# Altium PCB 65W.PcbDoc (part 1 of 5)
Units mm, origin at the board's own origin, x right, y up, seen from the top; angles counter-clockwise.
Board outline 240.2 x 292.5 mm, 2 copper layers (Top Layer, Bottom Layer); 57 components, 0 nets, 145 pads, 8 vias.

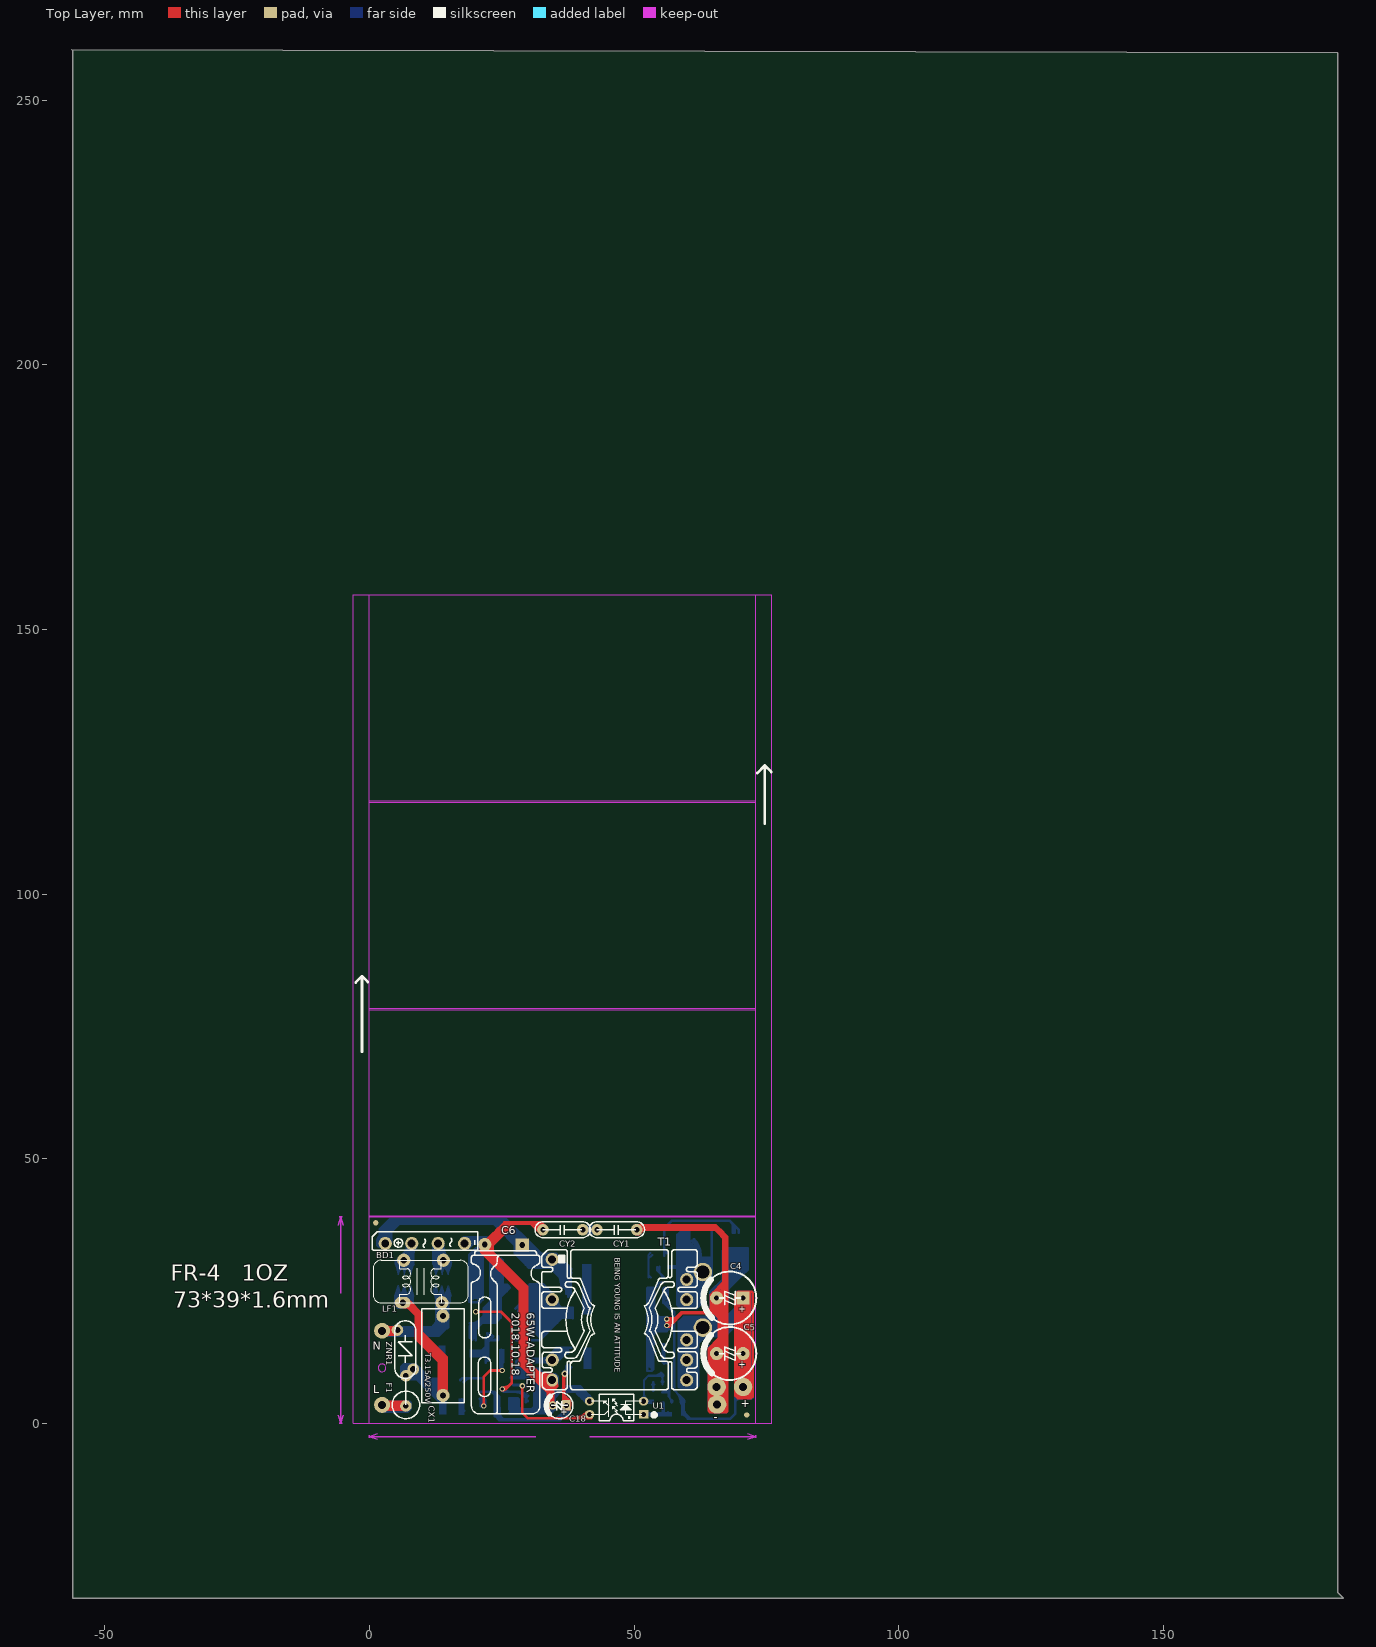
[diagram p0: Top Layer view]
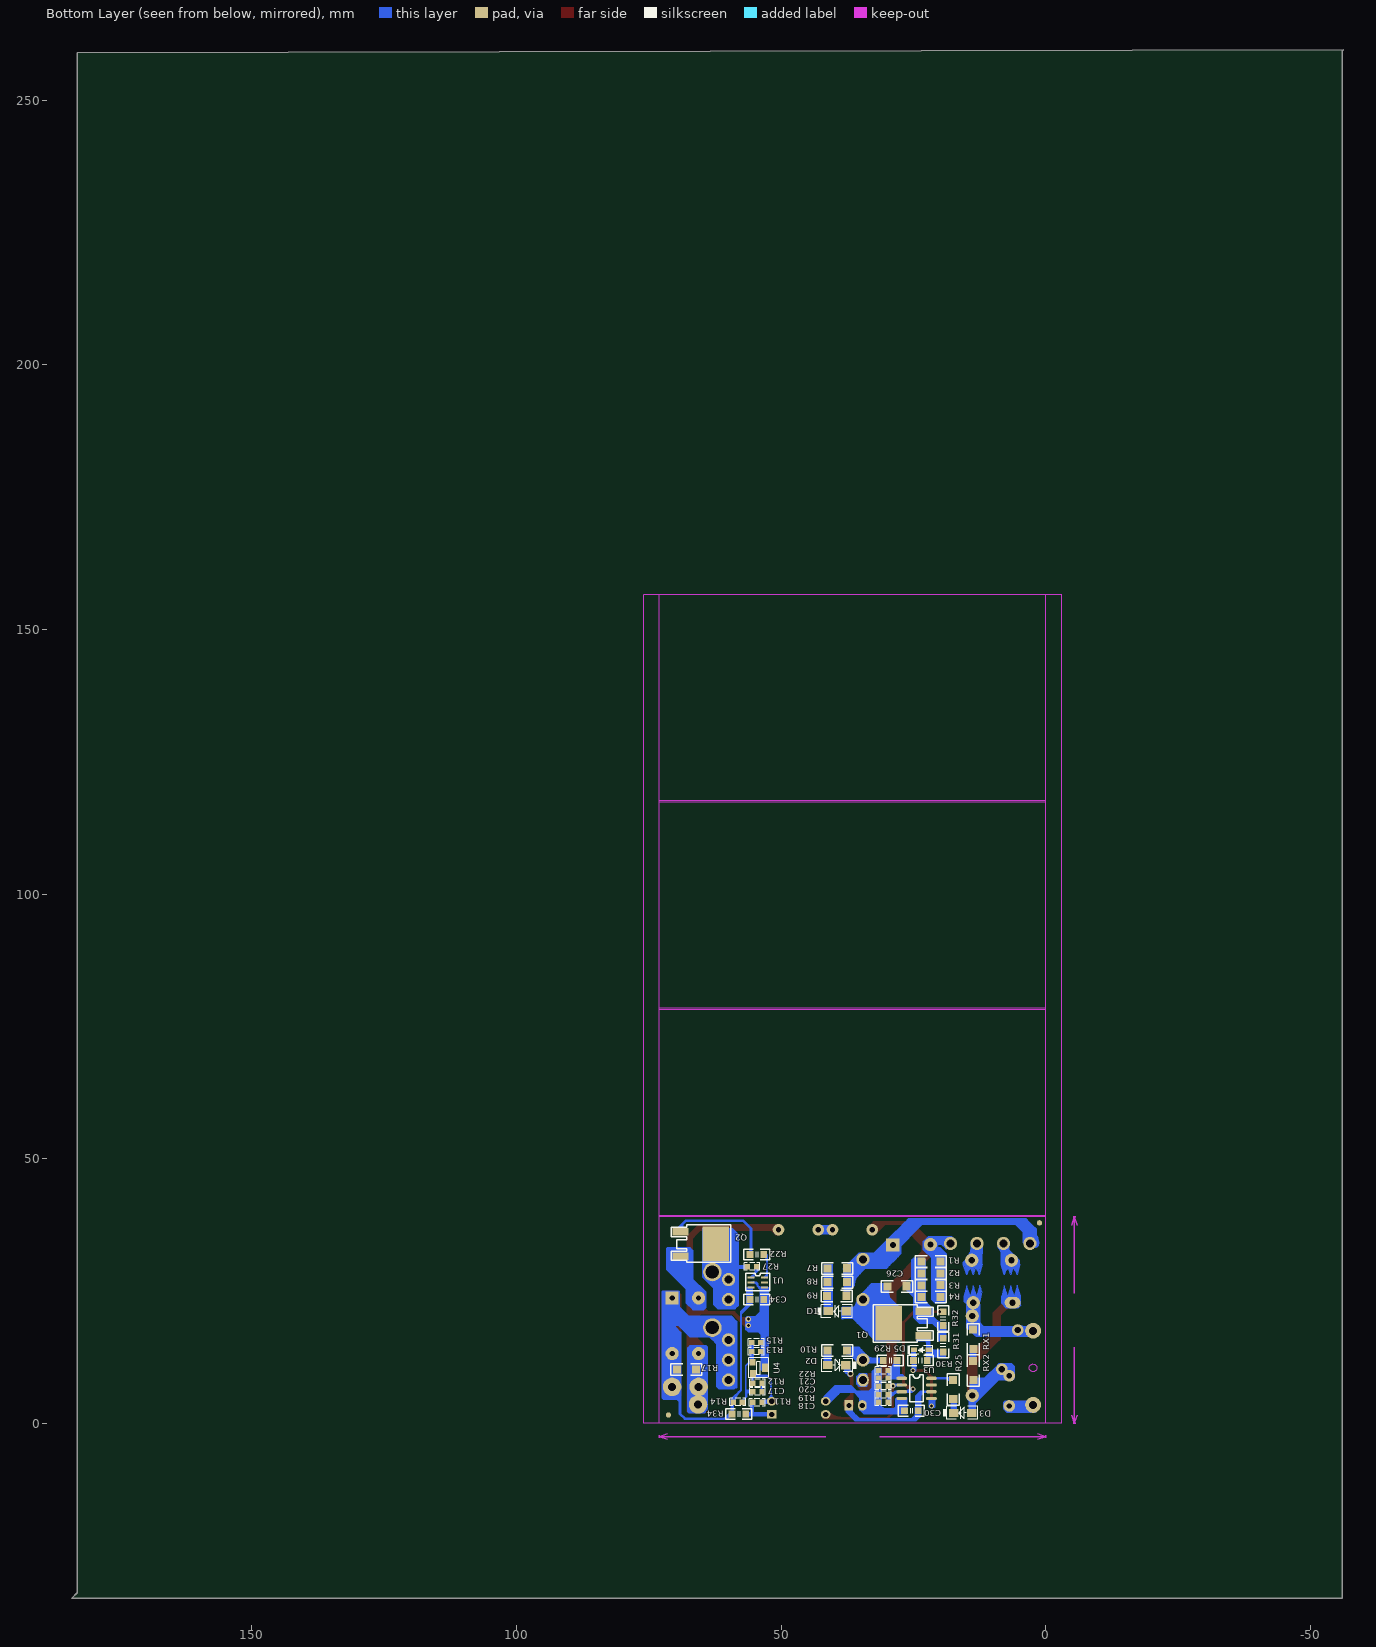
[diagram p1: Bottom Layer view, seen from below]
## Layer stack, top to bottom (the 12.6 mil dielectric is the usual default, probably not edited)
Top Layer: signal copper 0.0356
Dielectric: dielectric 0.32, FR-4, Dk 4.8
Bottom Layer: signal copper 0.0356

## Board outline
-56.2,259.5 -56,259.3 -56,-33 184,-33 183,-32 183,259

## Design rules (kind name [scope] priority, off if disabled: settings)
Clearance [All] p1: gap=0.254
PolygonConnect [All] p1: connectstyle=Relief reliefconductorwidth=0.254 reliefentries=4 polygonreliefangle="90 Angle"
RoutingVias [All] p1: holewidth=0.711 width=1.27 viastyle="Through Hole" minholewidth=0.711 minwidth=1.27 maxholewidth=0.711 maxwidth=1.27
SilkscreenOverComponentPads [All] p1: minsilkscreentomaskgap=0.254
SolderMaskExpansion [All] p1: expansion=0.102
TestPointUsage [All] p1: valid=0 allowmultiple=FALSE
Testpoint [All] p1: side=15 testpointundercomponent=TRUE minsize=1.016 maxsize=2.54 preferedsize=1.524 minholesize=0 maxholesize=1.016 preferedholesize=0.813 testpointgrid=0.025 style=1023 order=0-112345678
Width [All] p1: maxlimit=2 minlimit=0.1 preferedwidth=0.5
23 further rules are at their usual default settings.

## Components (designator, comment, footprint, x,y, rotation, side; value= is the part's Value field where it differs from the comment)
BD1 "" BD-GBL406L 3,34 r0 top
C4 "CAPACITOR+" EC10#1 70.6,23.7 r180 top
C5 "CAPACITOR+" EC10#2 70.6,13.2 r180 top (schematic designator C4)
C6 "" EC13*30 28.9,33.7 r270 top
C17 "" 0603 54.5,6 r180 bottom
C18 "CAPACITOR+" EC5 37.2,3.4 r180 top (schematic designator C9)
C18 "" 0603 30.7,4 r180 bottom
C20 "" 0603 30.7,7 r180 bottom
C21 "" 0603 30.7,8.6 r180 bottom
C26 "" 1206-S 28.1,25.9 r0 bottom
C30 "RESISTOR" 0805-S 25.4,2.4 r0 bottom (schematic designator R29)
C34 "RESISTOR" 0805-S 54.6,23.4 r0 bottom (schematic designator R29)
CX1 "CAPACITOR" C15 13.9,20.3 r270 top
CY1 "CAPACITOR" CY7.5 50.5,36.6 r180 top
CY2 "CAPACITOR" CY7.5 40.3,36.6 r180 top (schematic designator CY1)
D1 "" 4148 39.4,21.2 r180 bottom
D2 "" 4148 39.5,11 r0 bottom
D3 "" 4148 15.7,2 r180 bottom
D5 "DIODE" SOD-323 22.1,13.9 r0 bottom
F1 "FUSE" FUSE5220 6.9,3.5 r269 top
LF1 "TRANSFORMER" L18*8 13.7,22.8 r180 top
Q1 "" TO-252 23.1,16.6 r90 bottom
Q2 "" TO-252 69,36.2 r270 bottom
R1 "" 1206-S 21.7,30.6 r0 bottom
R2 "" 1206-S 21.7,28.3 r0 bottom
R3 "" 1206-S 21.7,26.1 r0 bottom
R4 "" 1206-S 21.7,23.9 r0 bottom
R7 "" 1206-S 39.4,29.3 r0 bottom
R8 "" 1206-S 39.4,26.7 r0 bottom
R9 "" 1206-S 39.5,24.1 r0 bottom
R10 "" 1206-S 39.4,13.8 r0 bottom
R11 "" 0603 54.5,4 r0 bottom
R12 "" 0603 54.5,7.6 r180 bottom
R13 "" 0603 54.7,13.6 r180 bottom
R14 "" 0603 58.2,4 r180 bottom
R15 "" 0603 54.7,15.3 r180 bottom
R17 "" 1206-S 67.9,10.2 r0 bottom
R19 "" 0603 30.7,5.4 r180 bottom
R22 "RESISTOR" 0805-S 54.6,31.9 r0 bottom (schematic designator R29)
R22 "" 0603 30.7,10 r180 bottom
R25 "" 1206-S 17.5,6.4 r90 bottom
R27 "" 0603 55.5,29.6 r180 bottom
R29 "RESISTOR" 0805-S 29.4,11.9 r0 bottom
R30 "RESISTOR" 0805-S 23.7,11.9 r180 bottom (schematic designator R29)
R31 "RESISTOR" 0805-S 19.4,14.8 r90 bottom (schematic designator R29)
R32 "RESISTOR" 0805-S 19.4,19.8 r90 bottom (schematic designator R29)
R34 "RESISTOR" 0805-S 58,1.8 r0 bottom (schematic designator R29)
RX1 "" 1206-S 13.7,15.9 r90 bottom
RX2 "" 1206-S 13.7,10 r90 bottom
T1 "" PQ2625 34.544,30.988 r0 top
U1 "PC817" oc-10.2 51.8,1.7 r180 top
U1 "" SOT23-6 55.7,27.6 r180 bottom
U3 "DIP8-L" SO-8 27.2,8.5 r180 bottom
U4 "" C1815 54.2,10.5 r270 bottom
ZNR1 "ZNR" ZNR7.5-2 5.3,10.3 r90 top
? "" ESD-1#1 13.7,27.4 r270 top
? "" ESD-1#2 6.6,27.4 r270 top

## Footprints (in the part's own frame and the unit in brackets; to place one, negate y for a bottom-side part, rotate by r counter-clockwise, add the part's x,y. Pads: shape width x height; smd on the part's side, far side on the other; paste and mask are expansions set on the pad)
0603 [mm]
  rect 1.016x1 smd: 1(-0.875,0) 2(0.875,0)
  silkscreen extent -1.48,-0.68 1.49,0.72
0805-S [mm]
  rect 1.27x1.27 smd: 1(-1.301,0) 2(1.301,0)
  silkscreen extent -2.42,-1.02 2.46,1.02
1206-S [mil]
  rect 60x60 smd: 1(-71.44,-0.61) 2(71.44,0.61)
  silkscreen extent -116,-43 116,45
4148 [mm]
  rect 1.8x1.524 smd: 1(1.705,-0.006) 2(-1.705,0.006)
  silkscreen extent -3.76,-1.23 2.85,1.21
BD-GBL406L [mm] "PY LOW VF"
  round 2.5 hole 1.5: 1(0,0) 2(5,0) 3(10,0) 4(15,0)
  silkscreen extent -2.5,-1.25 17.5,2.25
C15 [mm]
  round 2.5 hole 1.2: 1(0,0) 2(15.011,0)
  silkscreen extent -1.4,-4.01 16.41,4.01
C1815 [mm]
  rect 1.6x1.2 smd: A(-0.013,1.2)
  rect 1.26x1.1 smd: K(1.076,-1.15) R(-1.076,-1.2)
  silkscreen extent -1.88,-1.92 1.89,1.9
CY7.5 [mm]
  round 2.2 hole 1: 1(7.5,0) 2(0,0)
  silkscreen extent -1.5,-1.5 9,1.5
EC5 [mm]
  rect 1.6x2 hole 1: 1(0,0)
  round 1.6 / inner round 1.3 / far side oval 1.6x2 hole 1: 2(2.54,0)
  silkscreen extent -1.25,-2.5 3.76,2.5
EC10#1 [mm]
  rect 2.5x2.5 / inner rect 1.5x1.5 / far side rect 2.5x2.5 hole 1: 1(0,0)
  round 2.5 hole 1: 2(5,0)
  silkscreen extent -2.5,-5 7.5,5
EC10#2 [mm]
  round 2.5 hole 1: 1(0,0)
  round 2.5 / inner round 1.5 / far side round 2.5 hole 1: 2(5,0)
  silkscreen extent -2.5,-5 7.5,5
EC13*30 [mm]
  rect 2.5x2.5 hole 1.1: 1(0,0)
  round 2.5 hole 1.1: 2(-0.1,-7.1)
  silkscreen extent 1.1,-9.62 31.9,3.3
ESD-1#1 [mm]
  Bottom Layer lines w0.152: -4.644,-1.731 -4.634,-1.721 -2.672,-1.721 -0.711,-1.171 -2.662,-0.53 ; -2.622,-1.671 -2.622,1.861 -0.671,1.221 -2.632,0.671 ; 1.325,-1.184 3.287,-0.633 ; 3.297,-0.633 1.345,0.007 3.307,0.558 ; -2.652,-0.52 -0.691,0.03 -2.642,0.671 ; -2.532,0.56 -2.622,0.56 ; 3.317,0.568 1.365,1.208 3.327,1.759 ; -1.441,1.231 -1.301,1.231 -1.291,1.221 -1.321,1.221 -1.381,1.161 -1.511,1.161 -1.521,1.171 -1.521,1.311 -1.591,1.381 -1.691,1.381 -1.641,1.331 -1.641,1.181 -1.711,1.111 -1.741,1.111 -1.771,1.141 -1.771,1.331 -1.911,1.471 -1.941,1.471 -1.871,1.401 -1.871,1.081 -1.941,1.011 -2.032,1.011 -2.012,1.031 -2.012,1.431 -2.072,1.491 -2.152,1.491 -2.122,1.461 -2.122,0.991 -2.172,0.941 -2.242,0.941 -2.262,0.961 -2.262,1.501 -2.292,1.531 -2.392,1.531 -2.412,1.511 -2.412,0.931 -2.352,0.991 -2.352,1.591 -2.492,1.591 -2.512,1.571 -2.512,0.791 -2.462,0.791 -2.422,0.831 -2.372,0.831 -2.332,0.871 -2.232,0.871 -2.202,0.901 -2.102,0.901 -2.082,0.921 -1.961,0.921 -1.901,0.981 -1.751,0.981 -1.661,1.071 -1.341,1.071 -1.181,1.231 -0.961,1.231 -1.151,1.231 -1.251,1.331 -1.421,1.331 -1.541,1.451 -1.791,1.451 -1.891,1.551 -2.162,1.551 -2.322,1.711 -2.642,1.711 -2.692,1.661 -2.842,1.661
  Bottom Layer lines w0.254: -2.532,-1.531 -2.372,-1.531 -2.222,-1.381 -1.941,-1.381 -1.982,-1.421 -2.702,-1.421 ; 2.532,-1.421 2.422,-1.421 2.352,-1.351 2.082,-1.351 1.921,-1.191 1.641,-1.191 1.881,-1.191 1.961,-1.111 2.212,-1.111 2.322,-1.001 2.632,-1.001 2.692,-0.941 2.972,-0.941 3.172,-0.741 3.323,-0.741 ; 2.342,-1.211 2.352,-1.201 2.412,-1.201 2.442,-1.171 2.532,-1.171 2.462,-1.241 2.582,-1.361 2.702,-1.361 2.702,-1.131 2.772,-1.061 2.912,-1.061 2.832,-1.141 2.832,-1.391 2.852,-1.371 3.062,-1.371 3.052,-1.361 3.052,-1.071 3.232,-0.891 3.272,-0.891 3.222,-0.941 ; -2.312,-1.131 -1.721,-1.131 -1.691,-1.161 -1.781,-1.071 -2.082,-1.071 -2.192,-0.961 -2.442,-0.961 -2.472,-0.931 -2.472,-1.271 -2.482,-1.281 -1.821,-1.281 -1.791,-1.311 -1.581,-1.311 -1.491,-1.221 -1.101,-1.221 -1.041,-1.161 -1.131,-1.161 -1.151,-1.141 -1.311,-1.141 -1.331,-1.121 -1.431,-1.121 -1.481,-1.071 -1.571,-1.071 -1.681,-0.961 -1.871,-0.961 -1.941,-0.891 -2.062,-0.891 -2.122,-0.831 -2.252,-0.831 -2.352,-0.731 -2.592,-0.731 -2.622,-0.701 -2.622,-0.661 ; -2.622,-0.35 -2.542,-0.35 -2.492,-0.3 -2.292,-0.3 -2.232,-0.24 -2.042,-0.24 ; 2.832,-0.08 3.152,-0.08 3.162,-0.07 3.162,-0.23 2.722,-0.23 2.482,0.01 2.422,0.01 2.442,0.03 2.742,0.03 2.812,0.1 3.152,0.1 3.262,0.21 3.262,-0.4 3.232,-0.43 3.052,-0.43 3.022,-0.4 2.892,-0.4 2.792,-0.3 2.622,-0.3 2.502,-0.18 2.342,-0.18 2.222,-0.06 1.761,-0.06 1.691,0.01 1.891,0.01 1.911,0.03 2.052,0.03 2.112,0.09 2.262,0.09 2.312,0.14 2.442,0.14 2.502,0.2 2.672,0.2 2.712,0.24 2.822,0.24 2.882,0.3 3.082,0.3 3.242,0.46 3.272,0.46 ; -2.232,0 -2.272,0.04 -2.492,0.04 -2.622,-0.09 -2.622,-0.12 -1.681,-0.12 -1.501,-0.12 -1.411,-0.03 -1.141,-0.03 -1.051,0.06 -1.251,0.06 -1.271,0.08 -1.591,0.08 -1.611,0.1 ; 2.972,0.981 3.112,1.121 3.112,1.231 3.122,1.221 3.122,1.021 3.032,1.111 2.522,1.111 2.452,1.181 2.452,1.241 2.922,1.241 3.042,1.361 3.202,1.361 3.222,1.381 3.222,0.811 3.182,0.771 3.102,0.851 2.902,0.851 2.822,0.931 2.452,0.931 2.282,1.101 2.082,1.101 1.971,1.211 1.721,1.211 1.751,1.241 1.982,1.241 2.022,1.281 2.242,1.281 2.362,1.401 2.682,1.401 2.722,1.441 2.882,1.441 3.012,1.571 3.282,1.571 3.373,1.481 3.623,1.481
  Bottom Layer lines w0.508: -1.611,0.1 -1.951,0.1 -2.162,0.31 -2.572,0.31 -2.622,0.36 -2.622,0.52
ESD-1#2 [mm]
  Bottom Layer lines w0.152: 3.277,-1.824 1.325,-1.184 3.287,-0.633 ; 3.323,-1.821 3.323,1.711 ; -2.672,-1.721 -0.711,-1.171 -2.662,-0.53 ; -2.622,-1.671 -2.622,1.861 -2.201,1.723 -0.671,1.221 -2.632,0.671 ; 3.297,-0.633 1.345,0.007 3.307,0.558 ; -2.652,-0.52 -0.691,0.03 -2.642,0.671 ; -2.532,0.56 -2.622,0.56 ; 3.317,0.568 1.365,1.208 3.327,1.759 ; -1.441,1.231 -1.301,1.231 -1.291,1.221 -1.321,1.221 -1.381,1.161 -1.511,1.161 -1.521,1.171 -1.521,1.311 -1.591,1.381 -1.691,1.381 -1.641,1.331 -1.641,1.181 -1.711,1.111 -1.741,1.111 -1.771,1.141 -1.771,1.331 -1.911,1.471 -1.941,1.471 -1.871,1.401 -1.871,1.081 -1.941,1.011 -2.032,1.011 -2.012,1.031 -2.012,1.431 -2.072,1.491 -2.152,1.491 -2.122,1.461 -2.122,0.991 -2.172,0.941 -2.242,0.941 -2.262,0.961 -2.262,1.501 -2.292,1.531 -2.392,1.531 -2.412,1.511 -2.412,0.931 -2.352,0.991 -2.352,1.591 -2.492,1.591 -2.512,1.571 -2.512,0.791 -2.462,0.791 -2.422,0.831 -2.372,0.831 -2.332,0.871 -2.232,0.871 -2.202,0.901 -2.102,0.901 -2.082,0.921 -1.961,0.921 -1.901,0.981 -1.751,0.981 -1.661,1.071 -1.341,1.071 -1.181,1.231 -0.961,1.231 -1.151,1.231 -1.251,1.331 -1.421,1.331 -1.541,1.451 -1.791,1.451 -1.891,1.551 -2.162,1.551 -2.322,1.711 -2.642,1.711 -2.692,1.661
  Bottom Layer lines w0.254: -2.532,-1.531 -2.372,-1.531 -2.222,-1.381 -1.941,-1.381 -1.982,-1.421 -2.702,-1.421 ; 2.342,-1.211 2.352,-1.201 2.412,-1.201 2.442,-1.171 2.532,-1.171 2.462,-1.241 2.582,-1.361 2.702,-1.361 2.702,-1.131 2.772,-1.061 2.912,-1.061 2.832,-1.141 2.832,-1.391 2.852,-1.371 3.062,-1.371 3.052,-1.361 3.052,-1.071 3.232,-0.891 3.272,-0.891 3.222,-0.941 3.222,-1.641 3.252,-1.671 3.152,-1.671 3.042,-1.561 2.852,-1.561 2.822,-1.531 2.642,-1.531 2.532,-1.421 2.422,-1.421 2.352,-1.351 2.082,-1.351 1.921,-1.191 1.641,-1.191 1.881,-1.191 1.961,-1.111 2.212,-1.111 2.322,-1.001 2.632,-1.001 2.692,-0.941 2.972,-0.941 3.172,-0.741 3.323,-0.741 ; -2.312,-1.131 -1.721,-1.131 -1.691,-1.161 -1.781,-1.071 -2.082,-1.071 -2.192,-0.961 -2.442,-0.961 -2.472,-0.931 -2.472,-1.271 -2.482,-1.281 -1.821,-1.281 -1.791,-1.311 -1.581,-1.311 -1.491,-1.221 -1.101,-1.221 -1.041,-1.161 -1.131,-1.161 -1.151,-1.141 -1.311,-1.141 -1.331,-1.121 -1.431,-1.121 -1.481,-1.071 -1.571,-1.071 -1.681,-0.961 -1.871,-0.961 -1.941,-0.891 -2.062,-0.891 -2.122,-0.831 -2.252,-0.831 -2.352,-0.731 -2.592,-0.731 -2.622,-0.701 -2.622,-0.661 ; -2.622,-0.35 -2.542,-0.35 -2.492,-0.3 -2.292,-0.3 -2.232,-0.24 -2.042,-0.24 ; 2.832,-0.08 3.152,-0.08 3.162,-0.07 3.162,-0.23 2.722,-0.23 2.482,0.01 2.422,0.01 2.442,0.03 2.742,0.03 2.812,0.1 3.152,0.1 3.262,0.21 3.262,-0.4 3.232,-0.43 3.052,-0.43 3.022,-0.4 2.892,-0.4 2.792,-0.3 2.622,-0.3 2.502,-0.18 2.342,-0.18 2.222,-0.06 1.761,-0.06 1.691,0.01 1.891,0.01 1.911,0.03 2.052,0.03 2.112,0.09 2.262,0.09 2.312,0.14 2.442,0.14 2.502,0.2 2.672,0.2 2.712,0.24 2.822,0.24 2.882,0.3 3.082,0.3 3.242,0.46 3.272,0.46 ; -2.232,0 -2.272,0.04 -2.492,0.04 -2.622,-0.09 -2.622,-0.12 -1.681,-0.12 -1.501,-0.12 -1.411,-0.03 -1.141,-0.03 -1.051,0.06 -1.251,0.06 -1.271,0.08 -1.591,0.08 -1.611,0.1 ; 2.972,0.981 3.112,1.121 3.112,1.231 3.122,1.221 3.122,1.021 3.032,1.111 2.522,1.111 2.452,1.181 2.452,1.241 2.922,1.241 3.042,1.361 3.202,1.361 3.222,1.381 3.222,0.811 3.182,0.771 3.102,0.851 2.902,0.851 2.822,0.931 2.452,0.931 2.282,1.101 2.082,1.101 1.971,1.211 1.721,1.211 1.751,1.241 1.982,1.241 2.022,1.281 2.242,1.281 2.362,1.401 2.682,1.401 2.722,1.441 2.882,1.441 3.012,1.571 3.282,1.571 3.373,1.481 3.623,1.481
  Bottom Layer lines w0.508: -1.611,0.1 -1.951,0.1 -2.162,0.31 -2.572,0.31 -2.622,0.36 -2.622,0.52
FUSE5220 [mm]
  round 2.2 hole 1: 1(0.2,0.003) 2(-5.499,-0.096)
  silkscreen extent -5,-2.6 2.6,2.6
L18*8 [mm]
  round 2.5 hole 1.2: 1(0,0) 3(7.216,-8.024) 4(-0.284,-8.024)
  oval 3x2.2 hole 1.2: 2(7.416,-0.024)
  silkscreen extent -5,-8 13,0
oc-10.2 [mm] "opticalcoupler"
  rect 1.8x1.6 hole 1: 1(0,0)
  oval 1.8x1.6 hole 1: 2(0,-2.5) 3(10.2,-2.5) 4(10.2,0)
  silkscreen extent -2.2,-3.8 9.85,1.2
PQ2625 [mm]
  round 2.5 hole 1.5: 1(0,0) 3(0,-7.6) 5(0,-19) 7(25.4,-22.8) 8(25.4,-19) 9(25.4,-15.2) 10(25.4,-7.6) 11(25.4,-3.8)
  oval 2.2x2.5 hole 1.5: 6(0,-22.8)
  silkscreen extent -2,-24.66 27.41,1.86
SO-8 [mil]
  oval 80x24 smd: 1(0,1) 2(0,-49) 3(0,-99) 4(0,-149) 5(220,-149) 6(220,-99) 7(220,-49) 8(220,1)
  silkscreen extent 60,-174 160,26
SOD-323 [mm]
  rect 1.2x0.8 smd: 1(0,0) 2(2.8,0)
  silkscreen extent -0.78,-0.8 4.06,0.8
SOT23-6 [mm]
  rect 1.27x0.4 smd: 1(0,0) 2(0,-0.94) 3(0,-1.905)
  rect 1.3x0.4 smd: 4(2.54,-1.905) 5(2.54,-0.947) 6(2.54,0)
  silkscreen extent -1.02,-2.54 3.56,0.76
TO-252 [mm]
  rect 6.5x5 smd: C(2.29,6.6)
  rect 1.4x3 smd: E(4.58,0) G(0,0)
  silkscreen extent -1.31,-1.8 5.79,9.5
ZNR7.5-2 [mm]
  round 2.2 hole 1.2: 1(7.34,-0.004) 2(-0.06,-3.004)
  silkscreen extent -1.8,-3.5 9.1,0.5

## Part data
C30 C34 R22 R29 R30 R31 R32 R34: "resistor"

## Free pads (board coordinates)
  round 3 hole 1.5: 0(2.4,17.5) 1(2.4,3.5)
  round 3.5 hole 2.5: 0(63,18.1) 1(63,28.6)
  round 1 all layers, no hole: 1(71.3,1.6) 2(1.2,37.9)
  round 3.5 hole 1.5: 2(70.6,6.9) 3(65.6,6.9) 4(65.7,3.6)

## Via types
v1: diameter 1, hole 0.6, Top Layer to Bottom Layer, 7 vias
v2: diameter 1.2, hole 0.7, Top Layer to Bottom Layer, 1 vias

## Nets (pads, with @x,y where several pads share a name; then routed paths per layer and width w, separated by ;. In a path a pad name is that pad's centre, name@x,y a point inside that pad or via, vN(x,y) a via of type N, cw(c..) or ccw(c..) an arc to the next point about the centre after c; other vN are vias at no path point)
pads on no net: BD1.1 BD1.2 BD1.3 BD1.4 C4.1 C4.2 C5.1 C5.2 C6.1 C6.2 C17.1 C17.2 C18.1 C18.2 C20.1 C20.2 C21.1 C21.2 C26.1 C26.2 C30.1 C30.2 C34.1 C34.2 CX1.1 CX1.2 CY1.1 CY1.2 CY2.1 CY2.2 D1.1 D1.2 D2.1 D2.2 D3.1 D3.2 D5.1 D5.2 F1.1 F1.2 LF1.1 LF1.2 LF1.3 LF1.4 Q1.C Q1.E Q1.G Q2.C Q2.E Q2.G R1.1 R1.2 R2.1 R2.2 R3.1 R3.2 R4.1 R4.2 R7.1 R7.2 R8.1 R8.2 R9.1 R9.2 R10.1 R10.2 R11.1 R11.2 R12.1 R12.2 R13.1 R13.2 R14.1 R14.2 R15.1 R15.2 R17.1 R17.2 R19.1 R19.2 R22.1 R22.2 R25.1 R25.2 R27.1 R27.2 R29.1 R29.2 R30.1 R30.2 R31.1 R31.2 R32.1 R32.2 R34.1 R34.2 RX1.1 RX1.2 RX2.1 RX2.2 T1.1 T1.3 T1.5 T1.6 T1.7 T1.8 T1.9 T1.10 T1.11 U1.1 U1.2 U1.3 U1.4 U1.5 U1.6 U3.1 U3.2 U3.3 U3.4 U3.5 U3.6 U3.7 U3.8 U4.A U4.K U4.R ZNR1.1 ZNR1.2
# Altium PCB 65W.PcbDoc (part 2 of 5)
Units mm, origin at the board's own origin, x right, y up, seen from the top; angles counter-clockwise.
Board outline 240.2 x 292.5 mm, 2 copper layers (Top Layer, Bottom Layer); 57 components, 0 nets, 145 pads, 8 vias.

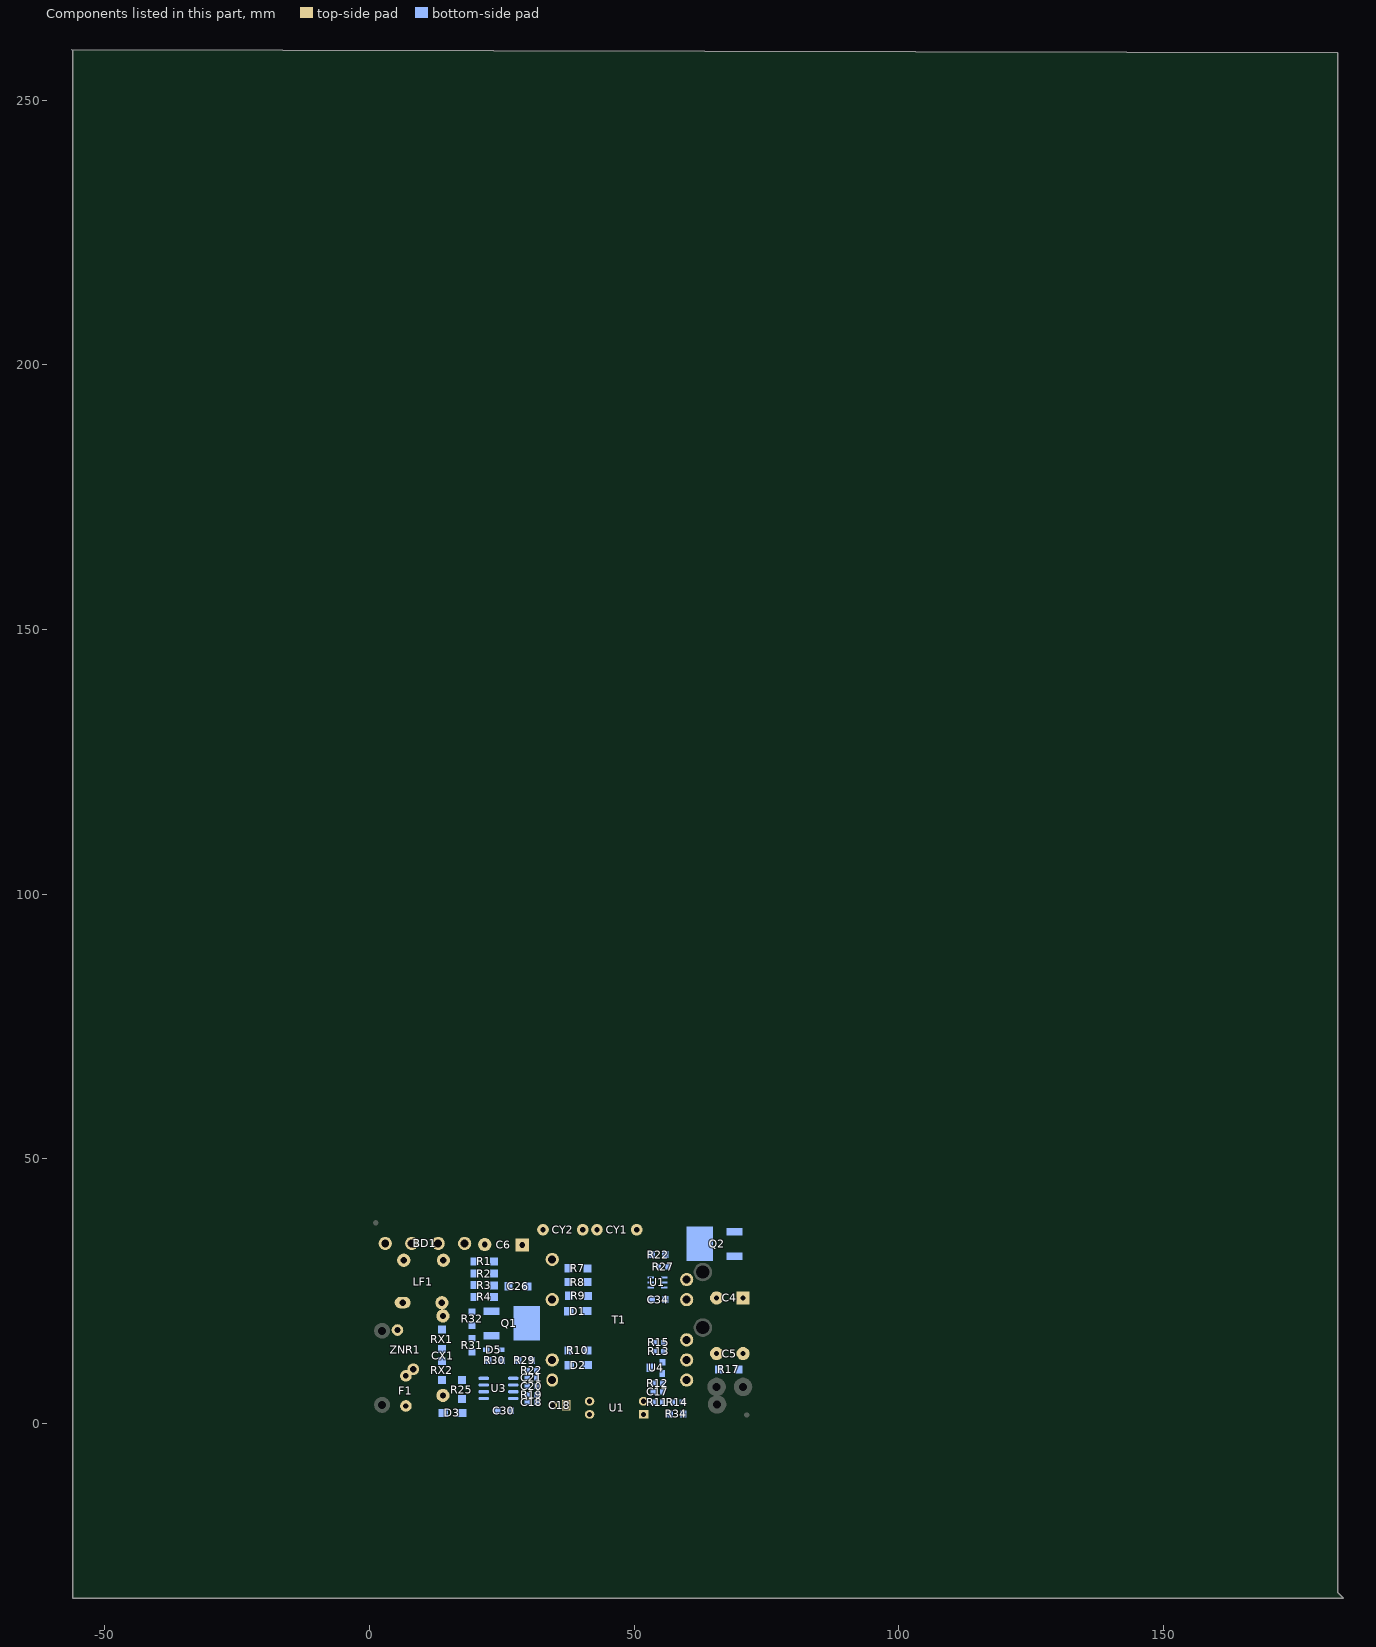
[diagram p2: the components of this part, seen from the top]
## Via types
v1: diameter 1, hole 0.6, Top Layer to Bottom Layer, 7 vias
v2: diameter 1.2, hole 0.7, Top Layer to Bottom Layer, 1 vias

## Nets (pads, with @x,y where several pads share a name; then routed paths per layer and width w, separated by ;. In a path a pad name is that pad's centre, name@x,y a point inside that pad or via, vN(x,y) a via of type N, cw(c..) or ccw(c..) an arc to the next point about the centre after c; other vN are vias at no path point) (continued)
copper on no net: | length 6106.5
  Top Layer w0.254: 5.644,17.6 5.704,17.54
  Top Layer w0.4: v1@56.1,18.3 56.2,18.2 56.6,18.2 ; v1@56.2,18.6 57,19.4 ; 56.2,19.2 56.4,19.4 57,19.4 ; 56.863,18.963 56.9,18.927 ; 57.3,19.4 57,19.4 ; 64.5,21 65.9,21 66.3,21.4 ; 64.5,21.4 63.9,20.8 63.6,20.8 ; 66.8,20.8 63.6,20.8 ; 56.6,18.2 56.9,18.5 ; 56.6,18.2 56.9,18.5 ; 56.9,18.5 59.2,20.8 60.8,20.8 63.6,20.8
  Top Layer w0.5: 3,16.8 4.164,16.8 ; 3,18.2 4.244,18.2 ; 5.1,18.2 4.244,18.2 ; 5.4,16.9 5.3,16.8 4.164,16.8 ; 6.284,22.824 6.876,22.824 ; 13.9,5.289 13.9,11.7 ; v1(20.1,21.1) 24.9,21.1 26.9,19.1 26.9,10.3 ; 21.3,33.7 21.3,33.8 ; v1(21.6,3.3) 21.6,8.8 22.8,10 v1(25.1,10) ; 21.656,34.156 25.5,38 30.4,38 ; 22.4,32.8 27.3,37.7 30.5,37.7 32.4,35.8 ; v1(25.1,6.5) 25.8,6.5 26.9,7.6 26.9,10.9 ; 26.6,37 23,33.4 21.9,33.4 ; v1(28.9,7.1) 28.9,2 29.9,1 39.9,1 ; 32.1,36.6 30.95,37.75 ; 32.4,37 31.75,37.65 ; 32.7,37.2 32.25,37.65 31.75,37.65 ; 33.5,37 32.5,38 30.4,38 ; 36.6,4.686 ccw(c38.086,4.686) 37.035,3.635 ; 36.6,5.894 ccw(c39.293,5.894) 37.389,3.989 ; 36.6,7.831 cw(c38.469,7.831) v2@37.147,9.153 ; 36.611,3.989 ccw(c36.195,4.405) 36.783,4.405 ; 36.7,2.9 36.6,3 36.6,9.1 v2(36.9,9.4) 36.783,9.283 36.783,8.1 ; 36.783,5.8 36.783,5.317 37.8,4.3 37.8,2.7 ; 36.783,8.674 cw(c37.232,8.674) v2@37.045,9.082 ; 36.804,4.696 cw(c36.167,4.059) 36.956,3.624 ; 37,4.3 37,3.4 ; 37.099,5.001 cw(c36.075,3.976) 37.417,3.431 ; v2@37.2,9.4 37.2,9.1 36.783,8.683 36.783,8.1 ; 37.3,3.1 37.3,4.2 36.783,4.717 36.783,5.4 ; 37.381,3.997 cw(c38.729,5.4) 36.783,5.4 ; 37.632,4.468 cw(c36.832,3.668) 37.88,3.242 ; 41.7,2.1 41.3,2.1 40.2,1 39.9,1 ; 42,1.1 41.9,1 40.4,1 ; 50.2,36.6 50.2,37.3 ; 50.4,35.8 51,35.8 51.8,36.6 53.2,36.6 ; 50.4,36.9 50.5,37 65.5,37 65.8,36.7 65.8,36.6 ; 50.5,36.6 53.2,36.6 ; 50.6,37.4 65.5,37.4 67.2,35.7 67.2,35.3 67.2,27 ; v1@56.1,19.9 56.15,19.85 57.75,19.85 ; v1(56.2,18.5) v1(56.2,19.7) ; v1@56.3,18.4 57.75,19.85 ; 64.5,21 64.5,21.3 ; 65.175,21.825 64.649,21.3 64.5,21.3 ; 65.2,20.8 66,20 66,19.8 ; 65.647,21.353 65.595,21.3 64.5,21.3 ; 66.5,25 66.9,25.4 66.9,35.5 ; 66.7,25.9 65.8,25 ; 67.2,35.2 66.9,35.5 ; 67.6,17.5 67.6,24 66.8,24.8 ; 67.6,23.4 67.6,35.3 66.3,36.6 65.8,36.6 ; 67.6,23.7 67.6,24.5 67.3,24.8 ; 67.6,34.3 65.3,36.6 64.4,36.6 ; 69.5,21.2 69.5,24.7 69.7,24.9 ; 70.5,24.9 69.7,24.9 ; 70.6,23.7 69.6,24.7 69.5,24.6 69.5,5 69.7,4.8 70.2,4.8 ; 70.8,10.7 72.2,9.3 72.2,5.5 71.8,5.1 ; 2.8,17.6 cw(c2.8,15.563) 4.285,16.958 ; 2.8,17.6 cw(c2.8,15.563) 4.285,16.958 ; 2.8,17.6 cw(c2.8,15.563) 4.285,16.958 ; 2.8,17.6 5.6,17.6 ; 2.93,18.03 ccw(c3.969,19.069) 3.969,17.6 ; 2.93,18.03 ccw(c3.969,19.069) 3.969,17.6 ; 2.93,18.03 ccw(c3.969,19.069) 3.969,17.6 ; 2.937,16.977 cw(c4.415,15.537) 4.415,17.6 ; 2.937,16.977 cw(c4.415,15.537) 4.415,17.6 ; 2.937,16.977 cw(c4.415,15.537) 4.415,17.6 ; 2.997,17.6 ccw(c2.997,19.447) 4.303,18.141 ; 2.997,17.6 ccw(c2.997,19.447) 4.303,18.141 ; 2.997,17.6 ccw(c2.997,19.447) 4.303,18.141 ; 3.284,18.384 ccw(c5.176,20.276) 5.176,17.6 ; 3.284,18.384 ccw(c5.176,20.276) 5.176,17.6 ; 3.284,18.384 ccw(c5.176,20.276) 5.176,17.6 ; 3.295,16.628 cw(c5.6,14.383) 5.6,17.6 ; 3.295,16.628 cw(c5.6,14.383) 5.6,17.6 ; 3.295,16.628 cw(c5.6,14.383) 5.6,17.6 ; 4.164,16.8 4.904,17.54 4.244,18.2 ; 13.193,5.996 ccw(c11.486,7.703) 13.9,7.703 ; 13.193,5.996 ccw(c11.486,7.703) 13.9,7.703 ; 13.193,5.996 ccw(c11.486,7.703) 13.9,7.703 ; 13.9,7.703 ccw(c16.314,7.703) 14.607,5.996 ; 13.9,7.703 ccw(c16.314,7.703) 14.607,5.996 ; 13.9,7.703 ccw(c16.314,7.703) 14.607,5.996 ; v1@20.277,20.923 cw(c20.704,20.496) 20.704,21.1 ; v1@20.277,20.923 cw(c20.704,20.496) 20.704,21.1 ; v1@20.277,20.923 cw(c20.704,20.496) 20.704,21.1 ; v1@20.277,21.277 ccw(c20.704,21.704) 20.704,21.1 ; v1@20.277,21.277 ccw(c20.704,21.704) 20.704,21.1 ; v1@20.277,21.277 ccw(c20.704,21.704) 20.704,21.1 ; v1@21.423,3.477 ccw(c20.996,3.904) 21.6,3.904 ; v1@21.423,3.477 ccw(c20.996,3.904) 21.6,3.904 ; v1@21.423,3.477 ccw(c20.996,3.904) 21.6,3.904 ; 21.6,3.904 ccw(c22.204,3.904) v1@21.777,3.477 ; 21.6,3.904 ccw(c22.204,3.904) v1@21.777,3.477 ; 21.6,3.904 ccw(c22.204,3.904) v1@21.777,3.477 ; 21.9,33.4 ccw(c21.9,36.056) 23.778,34.178 ; 21.9,33.4 ccw(c21.9,36.056) 23.778,34.178 ; 21.9,33.4 cw(c24.314,33.4) 22.607,35.107 ; 21.9,33.4 ccw(c21.9,36.056) 23.778,34.178 ; 21.9,33.4 cw(c24.314,33.4) 22.607,35.107 ; 21.9,33.4 ccw(c21.9,36.056) 23.778,34.178 ; 21.9,33.4 ccw(c21.9,36.056) 23.778,34.178 ; 21.9,33.4 cw(c24.314,33.4) 22.607,35.107 ; 21.9,33.4 ccw(c21.9,36.056) 23.778,34.178 ; 21.9,33.9 ccw(c21.9,37.763) 24.631,35.031 ; 21.9,33.9 ccw(c21.9,37.763) 24.631,35.031 ; 21.9,33.9 ccw(c21.9,37.763) 24.631,35.031 ; 21.9,33.9 ccw(c21.9,37.763) 24.631,35.031 ; 21.9,33.9 ccw(c21.9,37.763) 24.631,35.031 ; 21.9,33.9 ccw(c21.9,37.763) 24.631,35.031 ; 21.9,34.4 ccw(c21.9,39.47) 25.485,35.885 ; 21.9,34.4 ccw(c21.9,39.47) 25.485,35.885 ; 21.9,34.4 ccw(c21.9,39.47) 25.485,35.885 ; 21.9,34.4 ccw(c21.9,39.47) 25.485,35.885 ; 21.9,34.4 ccw(c21.9,39.47) 25.485,35.885 ; 21.9,34.4 ccw(c21.9,39.47) 25.485,35.885 ; 22.4,33.4 cw(c26.021,33.4) 23.461,35.961 ; 22.4,33.4 cw(c26.021,33.4) 23.461,35.961 ; 22.4,33.4 cw(c26.021,33.4) 23.461,35.961 ; 22.9,33.4 cw(c27.728,33.4) 24.314,36.814 ; 22.9,33.4 cw(c27.728,33.4) 24.314,36.814 ; 22.9,33.4 cw(c27.728,33.4) 24.314,36.814 ; 24.496,10 cw(c24.496,9.396) v1@24.923,9.823 ; 24.496,10 ccw(c24.496,10.604) v1@24.923,10.177 ; 24.496,10 ccw(c24.496,10.604) v1@24.923,10.177 ; 24.496,10 cw(c24.496,9.396) v1@24.923,9.823 ; 24.496,10 ccw(c24.496,10.604) v1@24.923,10.177 ; 24.496,10 cw(c24.496,9.396) v1@24.923,9.823 ; v1@25.1,6.25 ccw(c25.1,7.336) 25.868,6.568 ; v1@25.1,6.25 ccw(c25.1,7.336) 25.868,6.568 ; v1@25.1,6.25 ccw(c25.1,7.336) 25.868,6.568 ; v1@25.1,6.75 ccw(c25.1,9.043) 26.722,7.422 ; v1@25.1,6.75 ccw(c25.1,9.043) 26.722,7.422 ; v1@25.1,6.75 ccw(c25.1,9.043) 26.722,7.422 ; v1@25.277,6.323 cw(c25.704,5.896) 25.704,6.5 ; v1@25.277,6.323 cw(c25.704,5.896) 25.704,6.5 ; v1@25.277,6.323 cw(c25.704,5.896) 25.704,6.5 ; v1@25.277,6.677 ccw(c25.704,7.104) 25.704,6.5 ; v1@25.277,6.677 ccw(c25.704,7.104) 25.704,6.5 ; v1@25.277,6.677 ccw(c25.704,7.104) 25.704,6.5 ; v1@28.723,6.923 cw(c28.296,6.496) 28.9,6.496 ; v1@28.723,6.923 cw(c28.296,6.496) 28.9,6.496 ; v1@28.723,6.923 cw(c28.296,6.496) 28.9,6.496 ; 28.9,6.496 cw(c29.504,6.496) v1@29.077,6.923 ; 28.9,6.496 cw(c29.504,6.496) v1@29.077,6.923 ; 28.9,6.496 cw(c29.504,6.496) v1@29.077,6.923 ; 30.4,38 30.7,38 30.95,37.75 ; 30.95,37.75 31.45,37.75 31.65,37.75 31.75,37.65 ; 36.783,5.4 36.783,3.617 37,3.4 ; 36.783,5.4 36.783,8.1 ; 37,3.4 37.1,3.4 37.8,2.7 ; v2@37.147,9.153 ccw(c38.027,8.273) 36.783,8.273 cw(c38.027,8.273) v2@37.147,9.153 ; 37.8,2.7 37.3,2.7 37.8,2.7 ; 38.482,1 ccw(c38.482,4.718) 41.111,2.089 ; 38.482,1 ccw(c38.482,4.718) 41.111,2.089 ; 38.482,1 ccw(c38.482,4.718) 41.111,2.089 ; 39.689,1 ccw(c39.689,3.511) 41.465,1.735 ; 39.689,1 ccw(c39.689,3.511) 41.465,1.735 ; 39.689,1 ccw(c39.689,3.511) 41.465,1.735 ; 39.9,1 ccw(c39.9,2.099) 40.966,1.833 ; 39.9,1 ccw(c39.9,2.099) 40.966,1.833 ; 39.9,1 ccw(c39.9,2.099) 40.966,1.833 ; 39.9,1 40.9,1 ; 40.4,1 38.4,1 40.9,1 ; 40.4,1 40.9,1 ; 40.54,1 ccw(c40.54,1.939) 41.451,1.712 ; 40.54,1 ccw(c40.54,1.939) 41.451,1.712 ; 40.54,1 ccw(c40.54,1.939) 41.451,1.712 ; 40.567,1.367 cw(c41.297,0.638) 41.491,1.651 ; 40.567,1.367 cw(c41.297,0.638) 41.491,1.651 ; 40.567,1.367 cw(c41.297,0.638) 41.491,1.651 ; 40.896,1 ccw(c40.896,2.304) 41.818,1.382 ; 40.896,1 ccw(c40.896,2.304) 41.818,1.382 ; 40.896,1 ccw(c40.896,2.304) 41.818,1.382 ; 40.9,1 41.6,1.7 ; 40.9,1 41.6,1.7 ; 40.9,1 41.6,1.7 ; 53.2,36.6 63.6,36.6 ; 57.75,19.85 58.9,21 61,21 63.8,21 65.6,22.8 65.6,23.7 ; 63.6,36.6 65.8,36.6 ; 63.6,36.6 64.4,36.6 ; 64.4,36.6 65.8,36.6 ; 64.5,21.3 64.5,22.5 ; 64.5,22.5 66,21 66,19.8 ; 64.5,22.5 64.5,24.3 ; 64.5,24.3 65,24.8 66.8,24.8 ; 64.5,24.3 67.2,27 ; 65.6,23.7 65.6,23.6 67.6,21.6 67.6,2.3 67.4,2.1 64.4,2.1 64.1,2.4 64.1,14.1 66,16 66,19.8 ; 65.6,23.7 65.6,24.8 65.8,25 ; 65.8,25 67.1,25 67.2,24.9 ; 65.8,36.6 66.9,35.5 ; 66.8,24.8 67.3,24.8 ; 67.2,24.9 67.2,27 ; 67.2,24.9 67.3,24.8 ; 69.7,24.9 72.2,24.9 72.4,24.7 72.4,5.1 72.1,4.8 70.2,4.8 ; 69.7,24.9 69.1,24.3 69.1,5.3 69.6,4.8 70.2,4.8 ; 31.3,37.4 ccw(c31.87,37.97) 32.322,37.303 cw(c31.87,37.97) 31.3,37.4 ; 31.728,36.972 ccw(c32.216,37.46) 32.603,36.89 cw(c32.216,37.46) 31.728,36.972 ; 36.591,3.412 cw(c37.457,3.81) 36.783,4.483 ccw(c37.457,3.81) 36.591,3.412 ; 37,4.15 ccw(c37,4.754) 37.427,4.327 cw(c37,4.754) 37,4.15 ; 37.076,3.156 ccw(c36.929,4.015) 37.8,4.015 cw(c36.929,4.015) 37.076,3.156 ; 37.16,2.664 ccw(c37.03,3.422) 37.8,3.422 cw(c37.03,3.422) 37.16,2.664 ; 69.627,5.1 ccw(c69.627,6.976) 71.496,6.813 cw(c69.627,6.976) 69.627,5.1 ; 70.173,5.1 ccw(c70.173,6.929) 71.994,6.77 cw(c70.173,6.929) 70.173,5.1
  Top Layer w1: 2.2,3.8 6.4,3.8 6.9,3.3 2.6,3.3 2.585,3.315 ; 2.4,3.5 3.1,2.8 7,2.8 ; 7.3,22.5 9.6,20.2 9.6,17.2 14.4,12.4 14.4,6.4 13.9,5.9 13.9,5.289 ; 9.6,16.5 9.6,20.7 7.476,22.824 6.284,22.824 6.908,22.2 7.4,22.2 9,20.6 9,17.1 ; 13.4,5.2 13.4,11.7 9,16.1 9,17.1 ; 13.9,11.7 13.9,5.289 ; 21.3,33.7 21.3,32.6 28.7,25.2 28.7,24.8 ; 21.5,33 21.9,33.4 ; 21.65,33.4 ccw(c24.426,33.4) 22.463,31.437 ; 22.3,33.2 25.65,36.55 ; 22.833,34.333 23,34.166 23,32.3 ; 22.9,32.4 23,32.3 ; 24.17,29.73 cw(c27.841,33.4) 22.65,33.4 ; 25.96,37.46 25.65,37.15 ; 26.6,37.5 25.65,36.55 ; 29.1,21 29.1,12.1 32.4,8.8 ; 29.6,11.2 29.6,25.7 29.1,26.2 ; 34.1,3.2 34,3.3 34,5.4 34,5.9 32.65,7.25 32.45,7.45 28.7,11.2 28.7,24.8 ; 34.1,7.4 32.7,8.8 32.4,8.8 ; 34.4,8.5 34.46,8.44 34.46,5.3 ; 34.46,3.4 34.46,5 34.46,5.3 ; 34.544,8.188 33.932,8.8 33.2,8.8 32.4,8.8 ; 35.1,8.3 35.1,7.022 34.46,6.382 34.46,6.24 ; 6.684,22.224 cw(c6.684,20.553) 7.865,21.735 ; 6.684,22.224 cw(c6.684,18.863) 9.06,21.24 ; 6.684,22.224 cw(c6.684,20.071) 8.207,21.593 ; 6.684,22.224 cw(c6.684,20.553) 7.865,21.735 ; 6.684,22.224 cw(c6.684,18.863) 9.06,21.24 ; 6.684,22.224 cw(c6.684,20.071) 8.207,21.593 ; 6.684,22.224 cw(c6.684,20.553) 7.865,21.735 ; 6.684,22.224 cw(c6.684,18.863) 9.06,21.24 ; 6.684,22.224 cw(c6.684,20.071) 8.207,21.593 ; 7.284,22.824 ccw(c8.51,22.824) 7.643,21.957 ; 7.284,22.824 ccw(c8.51,22.824) 7.643,21.957 ; 7.284,22.824 ccw(c8.51,22.824) 7.643,21.957 ; 9,17.1 13.9,12.2 13.9,5.289 ; 13.37,5.819 ccw(c12.089,7.099) 13.9,7.099 ; 13.37,5.819 ccw(c12.089,7.099) 13.9,7.099 ; 13.37,5.819 ccw(c10.882,8.306) 14.4,8.306 ; 13.37,5.819 ccw(c12.089,7.099) 13.9,7.099 ; 13.37,5.819 ccw(c12.089,7.099) 13.9,7.099 ; 13.37,5.819 ccw(c10.882,8.306) 14.4,8.306 ; 13.37,5.819 ccw(c12.089,7.099) 13.9,7.099 ; 13.37,5.819 ccw(c12.089,7.099) 13.9,7.099 ; 13.37,5.819 ccw(c10.882,8.306) 14.4,8.306 ; 13.4,8.306 ccw(c16.918,8.306) 14.43,5.819 ; 13.4,8.306 ccw(c16.918,8.306) 14.43,5.819 ; 13.4,8.306 ccw(c16.918,8.306) 14.43,5.819 ; 13.9,7.099 ccw(c15.711,7.099) 14.43,5.819 ; 13.9,7.099 ccw(c15.711,7.099) 14.43,5.819 ; 13.9,7.099 ccw(c15.711,7.099) 14.43,5.819 ; 13.9,7.099 ccw(c15.711,7.099) 14.43,5.819 ; 13.9,7.099 ccw(c15.711,7.099) 14.43,5.819 ; 13.9,7.099 ccw(c15.711,7.099) 14.43,5.819 ; 21.9,32.65 cw(c21.9,30.839) 23.18,32.12 ; 21.9,32.65 cw(c21.9,30.839) 23.18,32.12 ; 21.9,32.65 cw(c21.9,30.839) 23.18,32.12 ; 21.9,33.4 25.65,37.15 ; 21.9,33.4 23,32.3 ; 21.9,33.4 21.9,32.6 28.7,25.8 28.7,24.8 ; 21.9,34.15 ccw(c21.9,35.961) 23.18,34.68 ; 21.9,34.15 ccw(c21.9,37.409) 24.205,35.105 ; 21.9,34.15 ccw(c21.9,35.961) 23.18,34.68 ; 21.9,34.15 ccw(c21.9,37.409) 24.205,35.105 ; 21.9,34.15 ccw(c21.9,35.961) 23.18,34.68 ; 21.9,34.15 ccw(c21.9,37.409) 24.205,35.105 ; 22.65,33.4 cw(c24.461,33.4) 23.18,34.68 ; 22.65,33.4 ccw(c26.392,33.4) 23.746,30.754 ; 22.65,33.4 ccw(c24.461,33.4) 23.18,32.12 ; 22.65,33.4 ccw(c26.392,33.4) 23.746,30.754 ; 22.65,33.4 ccw(c24.461,33.4) 23.18,32.12 ; 22.65,33.4 cw(c24.461,33.4) 23.18,34.68 ; 22.65,33.4 ccw(c26.392,33.4) 23.746,30.754 ; 22.65,33.4 ccw(c24.461,33.4) 23.18,32.12 ; 22.65,33.4 cw(c24.461,33.4) 23.18,34.68 ; 23,32.3 29.1,26.2 ; 25.65,36.55 25.65,37.15 ; 29.1,26.2 29.1,11.6 34.46,6.24 ; 30.116,10.584 ccw(c34.123,14.591) 34.495,8.936 ; 30.116,10.584 ccw(c34.123,14.591) 34.495,8.936 ; 30.116,10.584 ccw(c34.123,14.591) 34.495,8.936 ; 31.58,9.12 ccw(c33.05,10.59) 34.148,8.825 ; 31.58,9.12 ccw(c33.05,10.59) 34.148,8.825 ; 31.58,9.12 ccw(c33.05,10.59) 34.148,8.825 ; 31.676,9.024 ccw(c34.316,11.663) 34.56,7.939 ; 31.676,9.024 ccw(c34.316,11.663) 34.56,7.939 ; 31.676,9.024 ccw(c34.316,11.663) 34.56,7.939 ; 32.4,8.8 cw(c32.4,7.182) 33.865,7.869 ; 32.4,8.8 cw(c32.4,7.182) 33.865,7.869 ; 32.4,8.8 cw(c32.4,7.182) 33.865,7.869 ; 32.471,8.229 ccw(c33.733,9.491) 34.676,7.976 ; 32.471,8.229 ccw(c33.733,9.491) 34.676,7.976 ; 32.471,8.229 ccw(c33.733,9.491) 34.676,7.976 ; 33.237,7.463 ccw(c34.508,8.735) 34.626,6.941 ; 33.237,7.463 ccw(c34.508,8.735) 34.626,6.941 ; 33.237,7.463 ccw(c34.508,8.735) 34.626,6.941 ; 33.362,7.338 ccw(c34.416,8.393) 35.204,7.127 ; 33.362,7.338 ccw(c34.416,8.393) 35.204,7.127 ; 33.362,7.338 ccw(c34.416,8.393) 35.204,7.127 ; 34,5.235 ccw(c36.295,5.235) 34.672,3.612 ; 34,5.235 ccw(c36.295,5.235) 34.672,3.612 ; 34,5.235 ccw(c36.295,5.235) 34.672,3.612 ; 34.014,7.658 cw(c32.936,6.58) 34.46,6.58 ; 34.014,7.658 cw(c32.936,6.58) 34.46,6.58 ; 34.014,7.658 cw(c32.936,6.58) 34.46,6.58 ; 34.46,5.3 34.46,6.24 ; 34.46,6.175 cw(c36.557,6.175) 35.074,7.658 ; 34.46,6.175 cw(c36.557,6.175) 35.074,7.658 ; 34.46,6.175 cw(c36.557,6.175) 35.074,7.658
  Bottom Layer w0.152: 4.776,24.123 4.776,22.324 5.3,21.8 7.5,21.8 8.359,22.659 8.359,24.073 ; 4.879,30.072 4.879,30.779 5.8,31.7 8,31.7 ; 5.437,30.294 cw(c3.383,29.256) 5.57,28.538 ; 5.449,28.172 cw(c8.299,27.236) 6.945,29.913 ; 5.564,28.521 cw(c8.064,27.701) 6.876,30.049 ; 5.573,30.363 cw(c3.848,29.491) 5.684,28.888 ; 5.679,28.871 cw(c7.829,28.165) 6.807,30.185 ; 5.709,30.432 cw(c4.312,29.725) 5.799,29.237 ; 5.793,29.22 cw(c7.594,28.629) 6.739,30.321 ; 5.845,30.501 cw(c4.776,29.96) 5.914,29.587 ; 5.908,29.57 cw(c7.359,29.094) 6.67,30.457 ; 6.133,30.199 cw(c4.377,27.074) 7.829,28.042 ; 6.208,30.332 cw(c4.632,27.527) 7.729,28.397 ; 6.282,30.465 cw(c4.887,27.981) 7.63,28.751 ; 6.357,30.598 cw(c5.142,28.435) 7.531,29.105 ; 6.432,30.731 cw(c5.397,28.888) 7.431,29.459 ; 6.464,30.865 cw(c6.996,29.786) 7.847,30.637 ; 6.506,30.864 cw(c5.651,29.342) 7.332,29.813 ; 6.531,30.728 cw(c7.096,29.585) 7.997,30.486 ; 6.599,30.591 cw(c7.195,29.384) 8.147,30.336 ; 6.666,30.455 cw(c7.294,29.183) 8.298,30.186 ; 6.734,30.318 cw(c7.394,28.982) 8.448,30.036 ; 6.743,30.824 ccw(c7.546,30.825) 7.546,30.022 ; 6.896,30.824 ccw(c7.699,30.825) 7.699,30.022 ; 7.048,30.824 ccw(c7.851,30.825) 7.851,30.022 ; 7.17,33.17 cw(c4.052,30.052) 8.461,30.052 ; 7.2,33.3 8.2,33.3 ; 7.201,30.825 ccw(c8.004,30.825) 8.004,30.022 ; 7.278,33.278 cw(c4.42,30.42) 8.461,30.42 ; 7.319,29.859 cw(c7.907,30.025) 7.375,30.324 ; 7.353,30.825 ccw(c8.156,30.825) 8.156,30.022 ; 7.386,33.386 cw(c4.788,30.788) 8.461,30.788 ; 7.418,29.505 cw(c8.361,29.77) 7.507,30.249 ; 7.48,30.911 7.572,30.911 8.461,30.022 8.461,33.189 8.621,33.348 ; 7.493,33.493 cw(c5.156,31.156) 8.461,31.156 ; 7.505,30.825 ccw(c8.309,30.825) 8.309,30.022 ; 7.601,33.601 cw(c5.524,31.524) 8.461,31.524 ; 7.658,30.825 ccw(c8.461,30.826) 8.461,30.022 ; 7.709,33.709 cw(c5.892,31.892) 8.461,31.892 ; 7.817,33.817 cw(c6.26,32.26) 8.461,32.26 ; 7.924,33.924 cw(c6.628,32.628) 8.461,32.628 ; 8.261,30.092 8.261,30.561 ; 8.461,32.28 cw(c9.72,32.28) 8.83,33.17 ; 8.461,32.648 cw(c9.352,32.648) 8.722,33.278 ; 11.969,32.044 11.969,33.869 12.2,34.1 ; 11.969,32.094 cw(c13.006,32.094) 13.003,33.131 ; 11.969,32.247 cw(c13.005,32.247) 13.002,33.283 ; 11.969,32.4 cw(c13.005,32.4) 13.002,33.436 ; 11.969,32.553 cw(c13.004,32.553) 13.001,33.588 ; 11.969,32.705 cw(c13.004,32.705) 13.001,33.741 ; 11.969,32.858 cw(c13.003,32.858) 13,33.893 ; 11.969,33.011 cw(c13.003,33.011) 13,34.045 ; 11.969,33.164 cw(c13.002,33.164) 12.999,34.198 ; 12.031,17.999 ccw(c10.897,19.133) 12.5,19.133 ; 12.138,17.892 ccw(c11.265,18.765) 12.5,18.765 ; 12.246,17.784 ccw(c11.633,18.397) 12.5,18.397 ; 12.5,18.208 cw(c17.335,18.208) 14.334,21.999 ; 12.5,18.472 ccw(c13.473,18.472) 12.785,17.784 ; 12.5,18.523 cw(c17.086,18.523) 14.239,22.119 ; 12.5,18.838 cw(c16.836,18.838) 14.145,22.238 ; 12.5,18.84 ccw(c13.841,18.84) 12.893,17.892 ; 12.5,19.153 cw(c16.587,19.153) 14.05,22.358 ; 12.5,19.208 ccw(c14.209,19.208) 13,17.999 ; 12.5,19.468 cw(c16.337,19.468) 13.956,22.477 ; 12.5,19.783 cw(c16.088,19.783) 13.861,22.597 ; 12.5,20.098 cw(c15.839,20.098) 13.766,22.716 ; 12.5,20.413 cw(c15.589,20.413) 13.672,22.836 ; 12.5,20.728 cw(c15.34,20.728) 13.577,22.955 ; 12.5,21.043 cw(c15.091,21.043) 13.483,23.075 ; 12.5,21.358 cw(c14.841,21.358) 13.388,23.194 ; 12.5,21.673 cw(c14.592,21.673) 13.293,23.314 ; 12.5,21.988 cw(c14.342,21.988) 13.199,23.433 ; 12.5,22.304 cw(c14.093,22.304) 13.104,23.553 ; 12.5,23 12.1,24.9 12.2,25.4 12.516,26.075 ; 12.5,23.499 12.5,18.042 12.516,18.026 ; 12.531,28.118 cw(c15.915,27.007) 14.307,30.185 ; 12.646,28.467 cw(c15.68,27.472) 14.239,30.321 ; 12.761,28.817 cw(c15.445,27.936) 14.17,30.457 ; 12.876,29.166 cw(c15.21,28.4) 14.101,30.593 ; 12.937,30.294 cw(c12.041,29.841) 12.995,29.529 ; 12.99,29.516 cw(c14.975,28.864) 14.032,30.729 ; 13.073,30.363 cw(c12.506,30.076) 13.109,29.878 ; 13.105,29.865 cw(c14.74,29.329) 13.964,30.865 ; 13.484,29.933 cw(c12.012,27.313) 14.906,28.125 ; 13.558,30.066 cw(c12.266,27.766) 14.806,28.479 ; 13.633,30.199 cw(c12.521,28.22) 14.707,28.833 ; 13.708,30.332 cw(c12.776,28.674) 14.607,29.188 ; 13.782,30.465 cw(c13.031,29.127) 14.508,29.542 ; 13.984,32 15.561,30.423 15.561,30.022 ; 14.051,30.741 cw(c14.643,30.007) 15.31,30.674 ; 14.147,30.622 cw(c14.751,29.874) 15.43,30.554 ; 14.243,30.504 cw(c14.858,29.742) 15.55,30.434 ; 14.501,29.569 cw(c15.646,29.89) 14.609,30.473 ; 14.6,22.2 15.411,23.011 15.411,24.077 ; 14.6,29.214 cw(c16.1,29.635) 14.742,30.398 ; 14.699,28.86 cw(c16.554,29.381) 14.875,30.324 ; 14.799,28.506 cw(c17.007,29.126) 15.007,30.249
  Bottom Layer w0.254: 6.017,29.803 cw(c5.686,29.081) 6.48,29.081 cw(c7.268,29.081) 6.945,29.8 ; 6.122,30.034 cw(c5.867,29.477) 6.48,29.477 ; 6.127,29.759 cw(c6.019,29.436) 6.36,29.436 cw(c6.633,29.436) 6.604,29.707 ; 6.48,29.474 cw(c7.091,29.474) 6.84,30.031 ; 12.339,24.348 12.502,23.898 ; 12.5,23.499 12.502,23.898 ; 12.509,25.479 12.502,23.898 ; 13.46,29.378 ccw(c12.538,29.378) 13.19,30.03 cw(c12.248,29.088) 13.58,29.088 ; 13.58,29.035 cw(c14.268,29.035) 14.16,29.715 ; 13.58,29.333 cw(c14.221,29.333) 14.12,29.966 ; 13.58,29.63 cw(c14.174,29.63) 14.081,30.217
  Bottom Layer w0.35: 55.23,5.87 56.33,5.87 56.5,5.7 56.5,5.1 56.7,4.9 ; 55.4,11.576 56.024,11.576 ; 55.575,12 55.6,12 56.024,11.576 ; 55.6,11.576 55.805,11.781 55.805,14.77 ; 56.562,5.038 cw(c55.524,4) 56.992,4 ; 56.7,6 55.9,6 ; 56.7,7 56.7,6.4 56.5,6.2 ; 57.13,3.862 ccw(c55.662,3.862) 56.7,4.9 ; 57.325,4 57.325,4.275 ; 55.135,11.921 ccw(c54.072,12.984) 55.575,12.984 ; 55.135,11.921 ccw(c54.072,12.984) 55.575,12.984 ; 55.135,11.921 ccw(c54.072,12.984) 55.575,12.984 ; 55.135,11.921 ccw(c54.072,12.984) 55.575,12.984 ; 55.135,11.921 55.345,12.131 55.345,14.77 ; 55.345,13.17 cw(c54.79,12.615) 55.575,12.615 ; 55.345,13.17 cw(c54.79,12.615) 55.575,12.615 ; 55.345,13.17 cw(c54.79,12.615) 55.575,12.615 ; 55.345,13.17 cw(c54.79,12.615) 55.575,12.615 ; 55.345,13.63 ccw(c54.79,14.185) 55.575,14.185 ; 55.345,13.63 ccw(c54.79,14.185) 55.575,14.185 ; 55.345,13.63 ccw(c54.79,14.185) 55.575,14.185 ; 55.345,13.63 ccw(c54.79,14.185) 55.575,14.185 ; 55.345,14.77 cw(c54.79,14.215) 55.575,14.215 ; 55.345,14.77 cw(c54.79,14.215) 55.575,14.215 ; 55.345,14.77 cw(c54.79,14.215) 55.575,14.215 ; 55.345,14.77 cw(c54.79,14.215) 55.575,14.215 ; 55.575,11.325 55.65,11.4 56.2,11.4 ; 55.575,11.325 55.6,11.3 55.575,11.325 ; 55.575,11.325 55.575,15 55.575,11.325 ; 55.575,12.615 cw(c56.36,12.615) 55.805,13.17 ; 55.575,12.615 cw(c56.36,12.615) 55.805,13.17 ; 55.575,12.615 cw(c56.36,12.615) 55.805,13.17 ; 55.575,12.615 cw(c56.36,12.615) 55.805,13.17 ; 55.575,14.185 ccw(c56.36,14.185) 55.805,13.63 ; 55.575,14.185 ccw(c56.36,14.185) 55.805,13.63 ; 55.575,14.185 ccw(c56.36,14.185) 55.805,13.63 ; 55.575,14.185 ccw(c56.36,14.185) 55.805,13.63 ; 55.575,14.215 cw(c56.36,14.215) 55.805,14.77 ; 55.575,14.215 cw(c56.36,14.215) 55.805,14.77 ; 55.575,14.215 cw(c56.36,14.215) 55.805,14.77 ; 55.575,14.215 cw(c56.36,14.215) 55.805,14.77 ; 55.9,6 55.375,6 55.575,6.2 56.5,6.2 ; 55.9,6 56.3,6 56.5,6.2 ; 56.024,11.576 56.2,11.4 ; 56.2,11.4 cw(c56.2,11.94) 55.728,11.678 ccw(c56.2,11.94) 56.2,11.4 ; 56.2,11.4 56.7,10.9 56.7,5.3 ; 56.7,4.9 57.325,4.275 ; 56.7,4.9 56.7,5.3 ; 56.7,4.9 56.7,5.3 ; 56.7,4.9 57.325,4.275 ; 55.413,11.474 cw(c55.754,10.891) 56.231,11.369 ccw(c55.754,10.891) 55.413,11.474 ; 55.613,5.87 cw(c55.926,5.557) 55.926,6 ccw(c55.926,5.557) 55.613,5.87 ; 55.613,6.33 ccw(c56.409,7.126) 56.409,6 cw(c56.409,7.126) 55.613,6.33 ; 55.665,11.231 cw(c56.074,10.822) 56.074,11.4 ccw(c56.074,10.822) 55.665,11.231
  Bottom Layer w0.4: 51.8,1.7 51.9,1.8 56.699,1.8 ; 52.5,21.5 52.5,20.3 ; 52.7,27.6 52.7,28.7 ; 52.7,31.6 52.7,30.8 ; 52.8,9.9 53.2,9.9 53.7,10.4 53.7,14.2 ; 53.1,32.2 52.7,31.8 52.7,30.8 ; 53.16,25.695 54.195,25.695 54.5,26 ; 53.16,27.6 52.7,28.06 52.7,28.7 ; 53.4,25.695 53.395,25.7 52.6,25.7 52.5,25.6 52.5,25.4 ; 53.5,31.8 53.4,31.8 52.7,31.1 52.7,30.5 ; 53.625,6.1 53.625,7.8 ; 53.9,19.1 53.9,20.5 ; 53.9,21.8 53.9,20.9 53.9,20.1 54.3,19.7 ; 54.4,29.5 54.4,28.9 54.8,28.5 ; 54.625,29.4 54.625,28.675 ; 54.837,29.663 54.837,28.463 55,28.3 ; 55,19.7 54.7,19.7 53.9,20.5 ; 55.35,9.424 55.375,9.399 55.375,7.4 ; 55.4,1.8 55.375,1.825 55.375,4 55.7,3.675 55.7,1.8 ; 55.5,23.5 55.5,25.5 55.695,25.695 55.7,25.695 ; 55.5,23.8 55.5,22.8 57.6,20.7 57.6,20.3 57.6,19.8 ; 55.6,9 52.7,9 51.9,8.2 51.9,4.1 52,4 53.625,4 ; 55.7,27.6 55,28.3 ; 55.795,25.595 56.4,25.595 56.4,24.9 ; 56.3,23.4 55.901,23.4 56.4,23.899 56.4,24.9 ; 56.4,23.3 56.4,24.3 56.4,22.3 56.446,22.254 ; v1@56.6,18.6 56.6,19.9 56.4,20.1 54.8,20.1 53.8,21.1 53.8,22.7 ; v1@56.6,18.7 56.6,17.8 56.2,17.4 55.4,17.4 ; 58.56,24.86 58.6,24.9 ; 59.075,4 59.075,1.625 59.1,1.6 ; 59.275,4 59.275,4.625 ; 59.275,4.2 59.4,4.075 59.4,2.2 60.7,0.9 61.2,0.9 ; 59.301,1.8 60.201,0.9 60.5,0.9 61.2,0.9 ; 69.1,4.4 69.45,4.75 ; 69.1,6.4 69.1,3.7 ; 69.495,5.405 69.45,5.361 69.45,4.75 ; 70.6,6.9 70.6,5.9 69.45,4.75 ; 72.4,5.7 72.4,4.9 72.2,4.7 69.7,4.7 69.1,4.1 69.1,3.7 ; 51.9,5.649 cw(c50.451,5.649) 51.476,4.624 ccw(c50.451,5.649) 51.9,5.649 ; 51.9,5.649 ccw(c53.349,5.649) 52.324,4.624 cw(c53.349,5.649) 51.9,5.649 ; 52.5,20.3 52.5,9.9 53.4,9.9 53.4,16.5 ; 52.5,20.3 52.5,25.4 ; 52.5,25.4 ccw(c54.302,25.4) 53.494,23.789 cw(c54.302,25.4) 52.5,25.4 ; 52.5,25.4 52.5,23.3 52.5,22.8 52.6,22.7 53.8,22.7 ; 52.5,25.4 53.9,25.4 ; 52.7,28.7 52.7,30.5 ; 52.7,30.5 52.7,30.8 ; 52.717,10.996 ccw(c50.344,13.368) 53.7,13.368 cw(c50.344,13.368) 52.717,10.996 ; 52.717,10.996 ccw(c51.069,12.644) 53.4,12.644 cw(c51.069,12.644) 52.717,10.996 ; 52.893,4 cw(c52.893,3.276) 53.405,3.788 ccw(c52.893,3.276) 52.893,4 ; 52.893,4 ccw(c52.893,4.724) 53.405,4.212 cw(c52.893,4.724) 52.893,4 ; 53,10.713 ccw(c51.31,12.403) 53.7,12.403 cw(c51.31,12.403) 53,10.713 ; 53,10.713 cw(c54.207,11.92) 52.5,11.92 ccw(c54.207,11.92) 53,10.713 ; 53,10.713 ccw(c52.034,11.679) 53.4,11.679 cw(c52.034,11.679) 53,10.713 ; 53.4,16.5 ccw(c55.027,16.5) 54.005,15.233 cw(c55.027,16.5) 53.4,16.5 ; 53.4,16.5 53.7,16.8 ; 53.61,25.695 ccw(c53.743,26.757) 54.5,26 ; 53.61,25.695 cw(c52.91,24.995) 53.9,24.995 ccw(c52.91,24.995) 53.61,25.695 ; 53.61,25.695 ccw(c53.743,26.757) 54.5,26 ; 53.61,25.695 ccw(c53.743,26.757) 54.5,26 ; 53.61,25.695 ccw(c53.743,26.757) 54.5,26 ; 53.625,4 cw(c53.625,5.66) 52.358,4.588 ccw(c53.625,5.66) 53.625,4 ; 53.625,6.824 cw(c52.901,6.824) 53.413,6.312 ccw(c52.901,6.824) 53.625,6.824 ; 53.625,6.824 ccw(c54.349,6.824) 53.837,6.312 cw(c54.349,6.824) 53.625,6.824 ; 53.625,6.876 cw(c54.349,6.876) 53.837,7.388 ccw(c54.349,6.876) 53.625,6.876 ; 53.625,6.876 ccw(c52.901,6.876) 53.413,7.388 cw(c52.901,6.876) 53.625,6.876 ; 53.7,14.2 ccw(c54.376,14.2) 53.989,13.646 cw(c54.376,14.2) 53.7,14.2 ; 53.7,14.2 53.7,16.8 ; 53.7,16.8 54.3,17.4 ; 53.8,22.7 53.9,22.8 53.9,24.4 ; 53.9,20.5 53.9,24.4 ; 53.9,24.4 53.9,25.4 ; 53.9,25.4 cw(c51.886,25.4) 53.048,23.755 ccw(c51.886,25.4) 53.9,25.4 ; 53.9,25.4 54.5,26 ; 53.9,25.4 54.5,26 ; 54.3,17.4 ccw(c54.3,19.055) 55.669,18.125 cw(c54.3,19.055) 54.3,17.4 ; 54.3,17.4 55.4,17.4 ; 54.3,19.7 cw(c54.3,18.236) 55.635,18.836 ccw(c54.3,18.236) 54.3,19.7 ; 54.3,19.7 56.4,19.7 v1@56.6,19.5 ; 54.5,26 54.5,26.2 54.96,26.66 55.7,26.66 54.76,26.66 54.5,26.4 ; 54.5,26 54.5,26.4 ; 54.5,26 54.5,26.4 ; 54.625,28.676 cw(c55.349,28.676) 54.837,29.188 ccw(c55.349,28.676) 54.625,28.676 ; 54.625,28.676 ccw(c53.901,28.676) 54.413,29.188 cw(c53.901,28.676) 54.625,28.676 ; 54.625,28.675 54.8,28.5 ; 54.8,28.5 55,28.3 ; 55.265,26.66 ccw(c55.265,25.924) 54.745,26.445 cw(c55.265,25.924) 55.265,26.66 ; 55.265,26.66 ccw(c55.189,26.127) 54.808,26.508 cw(c55.189,26.127) 55.265,26.66 ; 55.375,3.276 cw(c56.099,3.276) 55.587,3.788 ccw(c56.099,3.276) 55.375,3.276 ; 55.375,3.276 ccw(c54.651,3.276) 55.163,3.788 cw(c54.651,3.276) 55.375,3.276 ; 55.375,8.324 cw(c54.651,8.324) 55.163,7.812 ccw(c54.651,8.324) 55.375,8.324 ; 55.375,8.324 ccw(c56.099,8.324) 55.587,7.812 cw(c56.099,8.324) 55.375,8.324 ; 55.4,17.4 55.6,17.4 56.6,18.4 v1@56.6,19.5 ; 55.649,1.8 cw(c55.649,0.75) 56.392,1.492 ccw(c55.649,0.75) 55.649,1.8 ; 55.649,1.8 ccw(c55.649,2.85) 56.392,2.108 cw(c55.649,2.85) 55.649,1.8 ; 55.7,25.695 55.7,23.2 55.7,23 57.6,21.1 57.6,19.8 ; 55.7,25.695 56.005,25.695 56.4,25.3 ; 56,17.9 ccw(c55.532,18.86) 56.6,18.86 cw(c55.532,18.86) 56,17.9 ; 56,17.9 cw(c55.056,18.542) 55.056,17.4 ccw(c55.056,18.542) 56,17.9 ; 56,19 ccw(c54.918,18.514) 54.918,19.7 cw(c54.918,18.514) 56,19 ; 56,19 cw(c55.76,18.195) 56.6,18.195 ccw(c55.76,18.195) 56,19 ; 56.4,24.9 56.4,25.3 ; 56.4,25.3 cw(c54.436,25.3) 55.635,23.744 ccw(c54.436,25.3) 56.4,25.3 ; v1@56.6,19.5 cw(c55.22,19.5) 55.825,18.26 ccw(c55.22,19.5) v1@56.6,19.5 ; 57.6,19.8 57.6,6.3 59.275,4.625 ; 59.075,3.276 cw(c59.799,3.276) 59.287,3.788 ccw(c59.799,3.276) 59.075,3.276 ; 59.075,3.276 ccw(c58.351,3.276) 58.863,3.788 cw(c58.351,3.276) 59.075,3.276 ; 59.275,4.625 cw(c58.932,4.625) 59.013,4.292 ccw(c58.932,4.625) 59.275,4.625 ; 61.2,0.9 68.2,0.9 69.1,1.8 69.1,3.7 ; 52.053,4.329 ccw(c52.762,4.93) 52.762,4 cw(c52.762,4.93) 52.053,4.329 ; 52.324,1.276 cw(c53.59,0.01) 53.59,1.8 ccw(c53.59,0.01) 52.324,1.276 ; 52.324,2.124 ccw(c53.107,2.907) 53.107,1.8 cw(c53.107,2.907) 52.324,2.124 ; 52.324,3.776 cw(c52.866,3.234) 52.866,4 ccw(c52.866,3.234) 52.324,3.776 ; 52.5,12.886 ccw(c55.173,12.886) 53.283,10.996 cw(c55.173,12.886) 52.5,12.886 ; 52.5,18.62 cw(c56.279,18.62) 53.607,21.292 ccw(c56.279,18.62) 52.5,18.62 ; 52.5,19.586 cw(c55.313,19.586) 53.324,21.575 ccw(c55.313,19.586) 52.5,19.586 ; 52.5,22.352 cw(c54.347,22.352) 53.041,23.658 ccw(c54.347,22.352) 52.5,22.352 ; 52.5,23.317 cw(c53.382,23.317) 52.758,23.941 ccw(c53.382,23.317) 52.5,23.317 ; 52.5,23.455 ccw(c53.327,23.455) 52.956,22.716 cw(c53.327,23.455) 52.5,23.455 ; 52.5,24.104 ccw(c53.652,24.104) 53.136,23.074 cw(c53.652,24.104) 52.5,24.104 ; 52.5,24.752 ccw(c53.977,24.752) 53.315,23.431 cw(c53.977,24.752) 52.5,24.752 ; 52.5,25.188 cw(c53.217,25.188) 52.71,25.695 ccw(c53.217,25.188) 52.5,25.188 ; 53.118,21.205 cw(c52.557,19.984) 53.9,19.984 ccw(c52.557,19.984) 53.118,21.205 ; 53.279,23.429 ccw(c52.432,24.628) 53.9,24.628 cw(c52.432,24.628) 53.279,23.429 ; 53.283,10.43 ccw(c52.276,11.437) 53.7,11.437 cw(c52.276,11.437) 53.283,10.43 ; 53.285,23.368 cw(c52.844,22.408) 53.9,22.408 ccw(c52.844,22.408) 53.285,23.368 ; 53.4,12.635 cw(c54.582,12.635) 53.746,13.471 ccw(c54.582,12.635) 53.4,12.635 ; 53.4,14.165 ccw(c54.582,14.165) 53.746,13.329 cw(c54.582,14.165) 53.4,14.165 ; 53.4,14.235 cw(c54.582,14.235) 53.746,15.071 ccw(c54.582,14.235) 53.4,14.235 ; 53.4,15.131 ccw(c55.548,15.131) 54.029,13.612 cw(c55.548,15.131) 53.4,15.131 ; 53.4,15.663 ccw(c54.352,15.663) 53.754,14.922 cw(c54.352,15.663) 53.4,15.663 ; 53.452,23.732 cw(c53.13,23.032) 53.9,23.032 ccw(c53.13,23.032) 53.452,23.732 ; 53.51,23.102 ccw(c52.978,23.855) 53.9,23.855 cw(c52.978,23.855) 53.51,23.102 ; 53.566,10.147 ccw(c53.241,10.471) 53.7,10.471 cw(c53.241,10.471) 53.566,10.147 ; 53.619,24.095 cw(c53.417,23.656) 53.9,23.656 ccw(c53.417,23.656) 53.619,24.095 ; 53.674,9 ccw(c53.674,11.02) 55.102,9.592 cw(c53.674,11.02) 53.674,9 ; 53.7,16.007 ccw(c54.824,16.007) 54.029,15.212 cw(c54.824,16.007) 53.7,16.007 ; 53.741,22.775 ccw(c53.523,23.083) 53.9,23.083 cw(c53.523,23.083) 53.741,22.775 ; 54.64,9 ccw(c54.64,10.054) 55.385,9.309 cw(c54.64,10.054) 54.64,9 ; 54.957,28.343 cw(c54.215,27.6) 55.265,27.6 ccw(c54.215,27.6) 54.957,28.343 ; 55.102,9.097 cw(c54.445,8.439) 55.375,8.439 ccw(c54.445,8.439) 55.102,9.097 ; 55.171,3.788 cw(c53.893,2.51) 55.7,2.51 ccw(c53.893,2.51) 55.171,3.788 ; 55.375,8.56 cw(c56.135,8.56) 55.597,9.097 ccw(c56.135,8.56) 55.375,8.56 ; 55.454,4.071 cw(c54.859,3.476) 55.7,3.476 ccw(c54.859,3.476) 55.454,4.071 ; 55.536,19.7 cw(c55.536,18.792) 56.365,19.164 ccw(c55.536,18.792) 55.536,19.7 ; 55.64,27.66 cw(c55.58,27.6) 55.665,27.6 ccw(c55.58,27.6) 55.64,27.66 ; 55.7,24.935 ccw(c57.436,24.935) 56.208,23.708 cw(c57.436,24.935) 55.7,24.935 ; 55.879,23.428 ccw(c55.063,24.486) 56.4,24.486 cw(c55.063,24.486) 55.879,23.428 ; v1@56.114,19.383 cw(c55.92,18.732) 56.6,18.732 ccw(c55.92,18.732) v1@56.114,19.383 ; 56.135,25.695 ccw(c56.449,25.695) 56.227,25.473 cw(c56.449,25.695) 56.135,25.695 ; 56.175,17.54 ccw(c55.844,18.22) 56.6,18.22 cw(c55.844,18.22) 56.175,17.54 ; 57.966,5.934 cw(c56.032,4) 58.767,4 ccw(c56.032,4) 57.966,5.934 ; 58.649,5.251 cw(c57.397,4) 59.167,4 ccw(c57.397,4) 58.649,5.251 ; 59.075,2.43 ccw(c59.93,2.43) 59.326,1.825 cw(c59.93,2.43) 59.075,2.43 ; 59.075,3.395 ccw(c60.896,3.395) 59.608,2.108 cw(c60.896,3.395) 59.075,3.395 ; 59.332,4.568 cw(c58.763,4) 59.567,4 ccw(c58.763,4) 59.332,4.568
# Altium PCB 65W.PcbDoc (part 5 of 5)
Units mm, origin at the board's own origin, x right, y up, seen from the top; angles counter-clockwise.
Board outline 240.2 x 292.5 mm, 2 copper layers (Top Layer, Bottom Layer); 57 components, 0 nets, 145 pads, 8 vias.

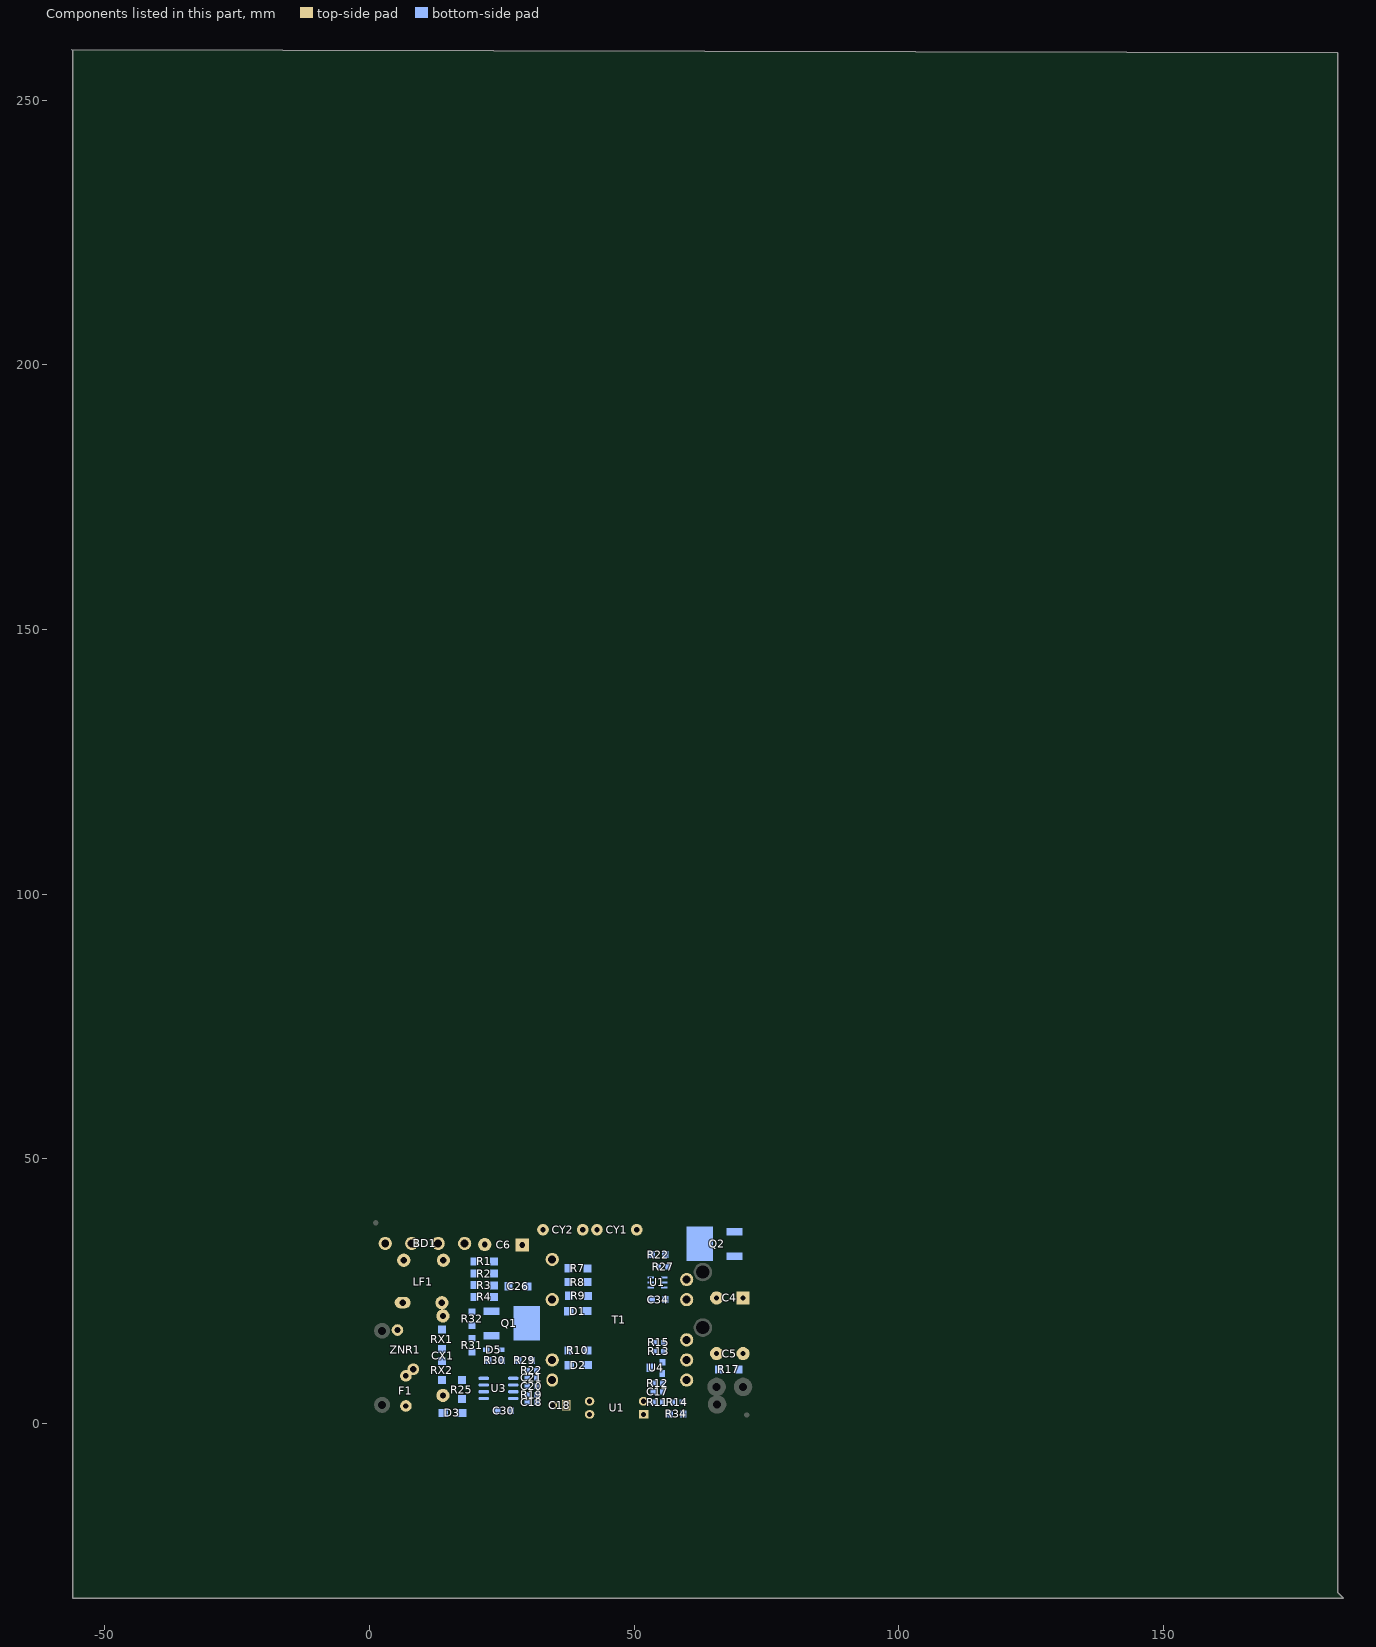
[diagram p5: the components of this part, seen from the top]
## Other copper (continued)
Bottom Layer:
  rectangle: 32.1,3.7 35,6.1
  region: 32.779,3.449 33.769,4.439 32.708,5.5 31.719,4.51
  rectangle: 31.9,2.5 34.7,4.4
  rectangle: 36.4,6 37.4,6.7
  rectangle: 39.6,6.2 40.1,7
  rectangle: 36.844,5.9 39.8,7
  region: 71.381,8.181 72.3,9.1 70.674,10.726 69.754,9.807
  rectangle: 69.17,8.4 71,10.37
  region: 7.55,21.85 8.359,22.659 7.864,23.154 7.055,22.345
  rectangle: 5.3,21.8 7.5,22.8
  rectangle: 4.776,22.659 8.359,24.123
  rectangle: 12.5,19.528 13.128,24.077
  rectangle: 15,22.793 15.193,22.887
  rectangle: 15,22.887 15.287,23.1
  rectangle: 14.2,22.7 15.1,23.3
  rectangle: 12.629,23.011 15.411,24.348
  rectangle: 14.4,30.022 15.561,30.5
  rectangle: 11.979,30.022 13.35,31.3
  rectangle: 7.324,29.892 8.191,30.824
  rectangle: 55.3,11.4 55.9,15.2
  rectangle: 51.6,3.7 53.8,4.5
  rectangle: 51.7,1.3 57.2,2.2
  region: 55.893,17.693 56.6,18.4 55.964,19.036 55.257,18.329
  region: 53.734,16.834 54.3,17.4 53.805,17.895 53.239,17.329
  rectangle: 53.2,17.4 55.6,18.8
  rectangle: 53.3,19.3 54.1,20.2
  rectangle: 53,18.4 56.6,19.7
  rectangle: 52.5,10.6 53.7,23.074
  rectangle: 56.3,29.2 58.9,29.9
  rectangle: 55.7,23.4 56.3,25.695
  rectangle: 52.5,23.3 53.9,25.4
  rectangle: 40,35.7 43.4,37.5
  rectangle: 29.8,30 33.8,30.988
  region: 63.169,16.169 64.3,17.3 63.31,18.29 62.179,17.159
  rectangle: 61.2,16.3 63.2,17.6
  region: 60.3,16.9 61.997,18.597 60.583,20.011 58.886,18.314
  rectangle: 58.9,6.7 61.7,18.4
  rectangle: 71.8,18.4 72.4,18.8
  rectangle: 71.4,18.4 72.1,19.3
  rectangle: 71.5,13.821 72.121,14.3
  rectangle: 71.5,13.638 71.938,14.3
  rectangle: 71.1,14.1 72.4,18.6
  rectangle: 69.9,13.407 71.707,19.1
  region: 67.75,17.35 70.55,20.15 69.122,21.578 66.322,18.778
  rectangle: 69.4,19.3 72.4,24.7
  rectangle: 60.5,17.3 67.7,19.8
  rectangle: 58.2,22.1 59.1,23.4
  rectangle: 58.8,21.8 61.2,23.5
  rectangle: 28.6,9.9 29.1,10.6
  rectangle: 28.099,9.9 28.7,10.9
  rectangle: 27.795,8.7 28.7,9.12
  rectangle: 28.099,8.525 29.45,10.2
  rectangle: 24.5,11.4 25.5,14.1
  rectangle: 16.8,1.6 18,4.7
  rectangle: 13.2,1.7 14.6,5.2
  rectangle: 13.1,11.4 14.4,14.7
  rectangle: 12.4,30.824 13.7,33.8
  rectangle: 18.9,23.5 21.4,31.9
  rectangle: 20.4,23.125 21.125,23.9
  rectangle: 20.1,31.9 21.8,33.1
  rectangle: 19.251,31.708 20.508,32.251
  rectangle: 19.847,31.914 20.714,32.847
  rectangle: 21.367,31.988 22.088,32.567
  rectangle: 19.5,31.9 20.1,32.6
  rectangle: 18.3,33.8 22,35.2
  rectangle: 21.4,33.9 22.5,34.9
  rectangle: 23.3,25.6 25,31.1
  rectangle: 24.1,20.14 24.64,20.7
  rectangle: 23.514,21.4 24.8,26
  region: 24.71,23.91 26.15,25.35 25.372,26.128 23.932,24.688
  region: 22.39,20.47 24.11,22.19 23.205,23.095 21.485,21.375
  rectangle: 29.914,16.8 33.2,25.884
  rectangle: 32.5,18.914 35.314,23.1
  region: 33.447,21.747 35.427,23.727 33.081,26.073 31.101,24.093
  region: 35.314,18.914 34.253,19.975 31.189,16.911 32.25,15.85
  rectangle: 28,31.3 28.9,32.4
  rectangle: 35,20 38.4,21.7
  rectangle: 35.5,19.649 36.049,22
  rectangle: 40.2,20.6 42,30.1
  region: 40.99,4.054 41.768,4.832 40,6.6 39.222,5.822
  rectangle: 40.5,10.3 42,14.3
  rectangle: 34.915,13.094 36.864,13.815
  rectangle: 34.616,12.1 35.8,13.516
  rectangle: 35.4,12.386 36.156,13.5
  rectangle: 35.8,12.73 36.5,13.516
  rectangle: 26.4,1.9 28.2,4.7
  rectangle: 27.6,1.9 34.3,2.8
  rectangle: 33.8,2.175 34.575,2.8
  rectangle: 18.9,12.5 22.399,14
  rectangle: 21.6,19.5 24.3,20.8
  rectangle: 21.3,19.4 22.2,20.1
  rectangle: 31.2,2.4 32.6,9.6
  rectangle: 31.721,9.2 32.5,9.791
  rectangle: 58.2,22.5 62.6,32.4
  rectangle: 61.3,27.4 64.7,31.5
  rectangle: 60.9,21.8 61.9,22.9
  region: 61.893,21.793 62.6,22.5 62.105,22.995 61.398,22.288
  rectangle: 59.112,34.7 60.7,36.512
  rectangle: 58.379,33.712 60.503,35.779
  rectangle: 58.7,35.5 59.8,36.2
  rectangle: 69.7,16 70.4,17.1
  rectangle: 69.126,20.7 70,21.726
  rectangle: 67.149,28.7 71.4,32.949
  rectangle: 64.4,21.8 66.8,24.8
  rectangle: 66.8,28.522 70.922,32.6
  rectangle: 64.7,22.8 67.8,25.1
  rectangle: 66.5,22.281 67.281,23
  rectangle: 66.8,25.952 68.352,29.2
  region: 70.9,28.5 69.4,30 64.684,25.284 66.184,23.784
  rectangle: 66.069,24.6 67.8,26.469
  rectangle: 69.2,5.9 72.4,15.1
  rectangle: 64.1,2.3 67.1,11.6
  rectangle: 64.1,10.9 66.7,14.4
  rectangle: 69.1,14.7 70.8,16.9

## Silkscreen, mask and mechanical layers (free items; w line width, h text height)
Top Overlay:
  lines w0.508: -2.6,83.3 -1.4,84.5 ; -1.4,70.2 -1.4,84.5 ; -0.3,83.4 -1.4,84.5 ; 73.3,122.9 74.7,124.3 ; 74.7,113.3 74.7,124.3 ; 74.7,124.2 74.7,124.3 ; 75.95,123.05 74.7,124.3
  text "BEING YOUNG IS AN ATTITUDE" at 46.4,31.3 h1 r270
  text "FR-4   1OZ" at -37.5,27 h3
  text "73*39*1.6mm" at -37.1,21.9 h3
  text "2018.10.18" at 26.9,20.9 h1.5 r270
  text "65W-ADAPTER" at 29.7,20.9 h1.5 r270
  text "N" at 0.6,13.9 h1.5
  text "T3.15A/250V" at 10.6,13.3 h1 r270
  text "L" at 0.7,5.7 h1.5
  text "+" at 70.2,3.1 h1.5
  text "-" at 65.1,0.5 h1.5
Bottom Paste:
  lines w0.5: 2.4,1.7 2.4,5.3 ; 2.4,15.7 2.4,19.3
  lines w0.6: 63.5,3.6 67.9,3.6 ; 68.8,6.9 72.6,6.9
Bottom Solder:
  region: 11.907,7.407 10.139,9.175 9.432,8.468 11.2,6.7
  rectangle: 7.4,16.8 9.9,18
  rectangle: 70.1,17.7 72.6,18.9
  rectangle: 66.5,18.8 69,20
  rectangle: 69.6,20.5 72.1,21.7
  region: 67.05,24.85 69.383,27.183 68.183,28.383 65.85,26.05
  rectangle: 33.6,19 35.4,21.4
  rectangle: 30.5,22.8 32.8,24.2
  rectangle: 31.7,24.8 32.8,26.1
  lines w0.8: 2.5,36.6 3.9,36.6 ; 4.4,38.1 25.6,38.1 ; 25.7,36.1 27.7,36.1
